VERSION 5.8 ;
BUSBITCHARS "[]" ;
DIVIDERCHAR "/" ;
UNITS
    DATABASE MICRONS 1000 ;
END UNITS

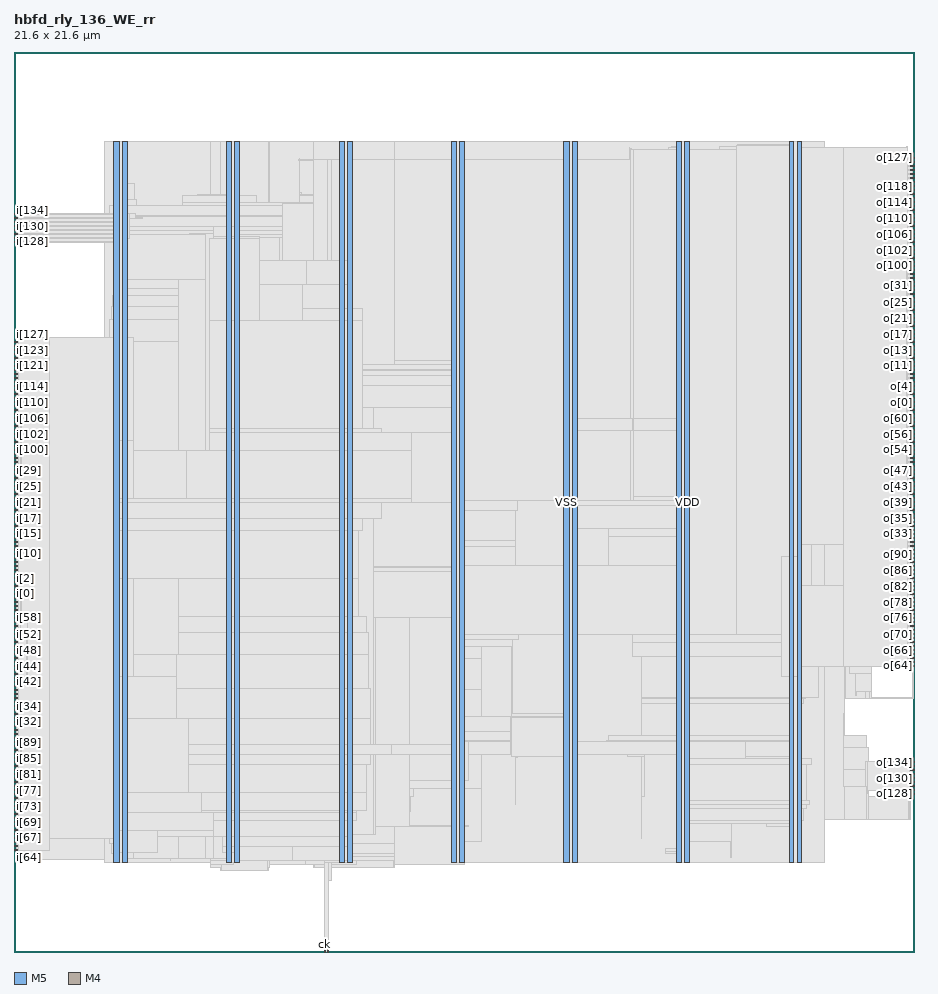
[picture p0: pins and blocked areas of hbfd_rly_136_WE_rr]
MACRO hbfd_rly_136_WE_rr
  FOREIGN hbfd_rly_136_WE_rr 0 0 ;
  CLASS BLOCK ;
  SIZE 21.6 BY 21.6 ;
  PIN ck
    DIRECTION INPUT ;
    USE SIGNAL ;
    PORT
      LAYER M5 ;
        RECT  7.44 0 7.464 0.084 ;
    END
  END ck
  PIN i[0]
    DIRECTION INPUT ;
    USE SIGNAL ;
    PORT
      LAYER M4 ;
        RECT  0 8.592 0.084 8.616 ;
    END
  END i[0]
  PIN i[100]
    DIRECTION INPUT ;
    USE SIGNAL ;
    PORT
      LAYER M4 ;
        RECT  0 12.048 0.084 12.072 ;
    END
  END i[100]
  PIN i[101]
    DIRECTION INPUT ;
    USE SIGNAL ;
    PORT
      LAYER M4 ;
        RECT  0 12.144 0.084 12.168 ;
    END
  END i[101]
  PIN i[102]
    DIRECTION INPUT ;
    USE SIGNAL ;
    PORT
      LAYER M4 ;
        RECT  0 12.24 0.084 12.264 ;
    END
  END i[102]
  PIN i[103]
    DIRECTION INPUT ;
    USE SIGNAL ;
    PORT
      LAYER M4 ;
        RECT  0 12.336 0.084 12.36 ;
    END
  END i[103]
  PIN i[104]
    DIRECTION INPUT ;
    USE SIGNAL ;
    PORT
      LAYER M4 ;
        RECT  0 12.432 0.084 12.456 ;
    END
  END i[104]
  PIN i[105]
    DIRECTION INPUT ;
    USE SIGNAL ;
    PORT
      LAYER M4 ;
        RECT  0 12.528 0.084 12.552 ;
    END
  END i[105]
  PIN i[106]
    DIRECTION INPUT ;
    USE SIGNAL ;
    PORT
      LAYER M4 ;
        RECT  0 12.624 0.084 12.648 ;
    END
  END i[106]
  PIN i[107]
    DIRECTION INPUT ;
    USE SIGNAL ;
    PORT
      LAYER M4 ;
        RECT  0 12.72 0.084 12.744 ;
    END
  END i[107]
  PIN i[108]
    DIRECTION INPUT ;
    USE SIGNAL ;
    PORT
      LAYER M4 ;
        RECT  0 12.816 0.084 12.84 ;
    END
  END i[108]
  PIN i[109]
    DIRECTION INPUT ;
    USE SIGNAL ;
    PORT
      LAYER M4 ;
        RECT  0 12.912 0.084 12.936 ;
    END
  END i[109]
  PIN i[10]
    DIRECTION INPUT ;
    USE SIGNAL ;
    PORT
      LAYER M4 ;
        RECT  0 9.552 0.084 9.576 ;
    END
  END i[10]
  PIN i[110]
    DIRECTION INPUT ;
    USE SIGNAL ;
    PORT
      LAYER M4 ;
        RECT  0 13.008 0.084 13.032 ;
    END
  END i[110]
  PIN i[111]
    DIRECTION INPUT ;
    USE SIGNAL ;
    PORT
      LAYER M4 ;
        RECT  0 13.104 0.084 13.128 ;
    END
  END i[111]
  PIN i[112]
    DIRECTION INPUT ;
    USE SIGNAL ;
    PORT
      LAYER M4 ;
        RECT  0 13.2 0.084 13.224 ;
    END
  END i[112]
  PIN i[113]
    DIRECTION INPUT ;
    USE SIGNAL ;
    PORT
      LAYER M4 ;
        RECT  0 13.296 0.084 13.32 ;
    END
  END i[113]
  PIN i[114]
    DIRECTION INPUT ;
    USE SIGNAL ;
    PORT
      LAYER M4 ;
        RECT  0 13.392 0.084 13.416 ;
    END
  END i[114]
  PIN i[115]
    DIRECTION INPUT ;
    USE SIGNAL ;
    PORT
      LAYER M4 ;
        RECT  0 13.488 0.084 13.512 ;
    END
  END i[115]
  PIN i[116]
    DIRECTION INPUT ;
    USE SIGNAL ;
    PORT
      LAYER M4 ;
        RECT  0 13.584 0.084 13.608 ;
    END
  END i[116]
  PIN i[117]
    DIRECTION INPUT ;
    USE SIGNAL ;
    PORT
      LAYER M4 ;
        RECT  0 13.68 0.084 13.704 ;
    END
  END i[117]
  PIN i[118]
    DIRECTION INPUT ;
    USE SIGNAL ;
    PORT
      LAYER M4 ;
        RECT  0 13.776 0.084 13.8 ;
    END
  END i[118]
  PIN i[119]
    DIRECTION INPUT ;
    USE SIGNAL ;
    PORT
      LAYER M4 ;
        RECT  0 13.872 0.084 13.896 ;
    END
  END i[119]
  PIN i[11]
    DIRECTION INPUT ;
    USE SIGNAL ;
    PORT
      LAYER M4 ;
        RECT  0 9.648 0.084 9.672 ;
    END
  END i[11]
  PIN i[120]
    DIRECTION INPUT ;
    USE SIGNAL ;
    PORT
      LAYER M4 ;
        RECT  0 13.968 0.084 13.992 ;
    END
  END i[120]
  PIN i[121]
    DIRECTION INPUT ;
    USE SIGNAL ;
    PORT
      LAYER M4 ;
        RECT  0 14.064 0.084 14.088 ;
    END
  END i[121]
  PIN i[122]
    DIRECTION INPUT ;
    USE SIGNAL ;
    PORT
      LAYER M4 ;
        RECT  0 14.16 0.084 14.184 ;
    END
  END i[122]
  PIN i[123]
    DIRECTION INPUT ;
    USE SIGNAL ;
    PORT
      LAYER M4 ;
        RECT  0 14.256 0.084 14.28 ;
    END
  END i[123]
  PIN i[124]
    DIRECTION INPUT ;
    USE SIGNAL ;
    PORT
      LAYER M4 ;
        RECT  0 14.352 0.084 14.376 ;
    END
  END i[124]
  PIN i[125]
    DIRECTION INPUT ;
    USE SIGNAL ;
    PORT
      LAYER M4 ;
        RECT  0 14.448 0.084 14.472 ;
    END
  END i[125]
  PIN i[126]
    DIRECTION INPUT ;
    USE SIGNAL ;
    PORT
      LAYER M4 ;
        RECT  0 14.544 0.084 14.568 ;
    END
  END i[126]
  PIN i[127]
    DIRECTION INPUT ;
    USE SIGNAL ;
    PORT
      LAYER M4 ;
        RECT  0 14.64 0.084 14.664 ;
    END
  END i[127]
  PIN i[128]
    DIRECTION INPUT ;
    USE SIGNAL ;
    PORT
      LAYER M4 ;
        RECT  0 17.04 0.084 17.064 ;
    END
  END i[128]
  PIN i[129]
    DIRECTION INPUT ;
    USE SIGNAL ;
    PORT
      LAYER M4 ;
        RECT  0 17.136 0.084 17.16 ;
    END
  END i[129]
  PIN i[12]
    DIRECTION INPUT ;
    USE SIGNAL ;
    PORT
      LAYER M4 ;
        RECT  0 9.744 0.084 9.768 ;
    END
  END i[12]
  PIN i[130]
    DIRECTION INPUT ;
    USE SIGNAL ;
    PORT
      LAYER M4 ;
        RECT  0 17.232 0.084 17.256 ;
    END
  END i[130]
  PIN i[131]
    DIRECTION INPUT ;
    USE SIGNAL ;
    PORT
      LAYER M4 ;
        RECT  0 17.328 0.084 17.352 ;
    END
  END i[131]
  PIN i[132]
    DIRECTION INPUT ;
    USE SIGNAL ;
    PORT
      LAYER M4 ;
        RECT  0 17.424 0.084 17.448 ;
    END
  END i[132]
  PIN i[133]
    DIRECTION INPUT ;
    USE SIGNAL ;
    PORT
      LAYER M4 ;
        RECT  0 17.52 0.084 17.544 ;
    END
  END i[133]
  PIN i[134]
    DIRECTION INPUT ;
    USE SIGNAL ;
    PORT
      LAYER M4 ;
        RECT  0 17.616 0.084 17.64 ;
    END
  END i[134]
  PIN i[135]
    DIRECTION INPUT ;
    USE SIGNAL ;
    PORT
      LAYER M4 ;
        RECT  0 17.712 0.084 17.736 ;
    END
  END i[135]
  PIN i[13]
    DIRECTION INPUT ;
    USE SIGNAL ;
    PORT
      LAYER M4 ;
        RECT  0 9.84 0.084 9.864 ;
    END
  END i[13]
  PIN i[14]
    DIRECTION INPUT ;
    USE SIGNAL ;
    PORT
      LAYER M4 ;
        RECT  0 9.936 0.084 9.96 ;
    END
  END i[14]
  PIN i[15]
    DIRECTION INPUT ;
    USE SIGNAL ;
    PORT
      LAYER M4 ;
        RECT  0 10.032 0.084 10.056 ;
    END
  END i[15]
  PIN i[16]
    DIRECTION INPUT ;
    USE SIGNAL ;
    PORT
      LAYER M4 ;
        RECT  0 10.128 0.084 10.152 ;
    END
  END i[16]
  PIN i[17]
    DIRECTION INPUT ;
    USE SIGNAL ;
    PORT
      LAYER M4 ;
        RECT  0 10.224 0.084 10.248 ;
    END
  END i[17]
  PIN i[18]
    DIRECTION INPUT ;
    USE SIGNAL ;
    PORT
      LAYER M4 ;
        RECT  0 10.32 0.084 10.344 ;
    END
  END i[18]
  PIN i[19]
    DIRECTION INPUT ;
    USE SIGNAL ;
    PORT
      LAYER M4 ;
        RECT  0 10.416 0.084 10.44 ;
    END
  END i[19]
  PIN i[1]
    DIRECTION INPUT ;
    USE SIGNAL ;
    PORT
      LAYER M4 ;
        RECT  0 8.688 0.084 8.712 ;
    END
  END i[1]
  PIN i[20]
    DIRECTION INPUT ;
    USE SIGNAL ;
    PORT
      LAYER M4 ;
        RECT  0 10.512 0.084 10.536 ;
    END
  END i[20]
  PIN i[21]
    DIRECTION INPUT ;
    USE SIGNAL ;
    PORT
      LAYER M4 ;
        RECT  0 10.608 0.084 10.632 ;
    END
  END i[21]
  PIN i[22]
    DIRECTION INPUT ;
    USE SIGNAL ;
    PORT
      LAYER M4 ;
        RECT  0 10.704 0.084 10.728 ;
    END
  END i[22]
  PIN i[23]
    DIRECTION INPUT ;
    USE SIGNAL ;
    PORT
      LAYER M4 ;
        RECT  0 10.8 0.084 10.824 ;
    END
  END i[23]
  PIN i[24]
    DIRECTION INPUT ;
    USE SIGNAL ;
    PORT
      LAYER M4 ;
        RECT  0 10.896 0.084 10.92 ;
    END
  END i[24]
  PIN i[25]
    DIRECTION INPUT ;
    USE SIGNAL ;
    PORT
      LAYER M4 ;
        RECT  0 10.992 0.084 11.016 ;
    END
  END i[25]
  PIN i[26]
    DIRECTION INPUT ;
    USE SIGNAL ;
    PORT
      LAYER M4 ;
        RECT  0 11.088 0.084 11.112 ;
    END
  END i[26]
  PIN i[27]
    DIRECTION INPUT ;
    USE SIGNAL ;
    PORT
      LAYER M4 ;
        RECT  0 11.184 0.084 11.208 ;
    END
  END i[27]
  PIN i[28]
    DIRECTION INPUT ;
    USE SIGNAL ;
    PORT
      LAYER M4 ;
        RECT  0 11.28 0.084 11.304 ;
    END
  END i[28]
  PIN i[29]
    DIRECTION INPUT ;
    USE SIGNAL ;
    PORT
      LAYER M4 ;
        RECT  0 11.376 0.084 11.4 ;
    END
  END i[29]
  PIN i[2]
    DIRECTION INPUT ;
    USE SIGNAL ;
    PORT
      LAYER M4 ;
        RECT  0 8.784 0.084 8.808 ;
    END
  END i[2]
  PIN i[30]
    DIRECTION INPUT ;
    USE SIGNAL ;
    PORT
      LAYER M4 ;
        RECT  0 11.472 0.084 11.496 ;
    END
  END i[30]
  PIN i[31]
    DIRECTION INPUT ;
    USE SIGNAL ;
    PORT
      LAYER M4 ;
        RECT  0 11.568 0.084 11.592 ;
    END
  END i[31]
  PIN i[32]
    DIRECTION INPUT ;
    USE SIGNAL ;
    PORT
      LAYER M4 ;
        RECT  0 5.52 0.084 5.544 ;
    END
  END i[32]
  PIN i[33]
    DIRECTION INPUT ;
    USE SIGNAL ;
    PORT
      LAYER M4 ;
        RECT  0 5.616 0.084 5.64 ;
    END
  END i[33]
  PIN i[34]
    DIRECTION INPUT ;
    USE SIGNAL ;
    PORT
      LAYER M4 ;
        RECT  0 5.712 0.084 5.736 ;
    END
  END i[34]
  PIN i[35]
    DIRECTION INPUT ;
    USE SIGNAL ;
    PORT
      LAYER M4 ;
        RECT  0 5.808 0.084 5.832 ;
    END
  END i[35]
  PIN i[36]
    DIRECTION INPUT ;
    USE SIGNAL ;
    PORT
      LAYER M4 ;
        RECT  0 5.904 0.084 5.928 ;
    END
  END i[36]
  PIN i[37]
    DIRECTION INPUT ;
    USE SIGNAL ;
    PORT
      LAYER M4 ;
        RECT  0 6 0.084 6.024 ;
    END
  END i[37]
  PIN i[38]
    DIRECTION INPUT ;
    USE SIGNAL ;
    PORT
      LAYER M4 ;
        RECT  0 6.096 0.084 6.12 ;
    END
  END i[38]
  PIN i[39]
    DIRECTION INPUT ;
    USE SIGNAL ;
    PORT
      LAYER M4 ;
        RECT  0 6.192 0.084 6.216 ;
    END
  END i[39]
  PIN i[3]
    DIRECTION INPUT ;
    USE SIGNAL ;
    PORT
      LAYER M4 ;
        RECT  0 8.88 0.084 8.904 ;
    END
  END i[3]
  PIN i[40]
    DIRECTION INPUT ;
    USE SIGNAL ;
    PORT
      LAYER M4 ;
        RECT  0 6.288 0.084 6.312 ;
    END
  END i[40]
  PIN i[41]
    DIRECTION INPUT ;
    USE SIGNAL ;
    PORT
      LAYER M4 ;
        RECT  0 6.384 0.084 6.408 ;
    END
  END i[41]
  PIN i[42]
    DIRECTION INPUT ;
    USE SIGNAL ;
    PORT
      LAYER M4 ;
        RECT  0 6.48 0.084 6.504 ;
    END
  END i[42]
  PIN i[43]
    DIRECTION INPUT ;
    USE SIGNAL ;
    PORT
      LAYER M4 ;
        RECT  0 6.576 0.084 6.6 ;
    END
  END i[43]
  PIN i[44]
    DIRECTION INPUT ;
    USE SIGNAL ;
    PORT
      LAYER M4 ;
        RECT  0 6.672 0.084 6.696 ;
    END
  END i[44]
  PIN i[45]
    DIRECTION INPUT ;
    USE SIGNAL ;
    PORT
      LAYER M4 ;
        RECT  0 6.768 0.084 6.792 ;
    END
  END i[45]
  PIN i[46]
    DIRECTION INPUT ;
    USE SIGNAL ;
    PORT
      LAYER M4 ;
        RECT  0 6.864 0.084 6.888 ;
    END
  END i[46]
  PIN i[47]
    DIRECTION INPUT ;
    USE SIGNAL ;
    PORT
      LAYER M4 ;
        RECT  0 6.96 0.084 6.984 ;
    END
  END i[47]
  PIN i[48]
    DIRECTION INPUT ;
    USE SIGNAL ;
    PORT
      LAYER M4 ;
        RECT  0 7.056 0.084 7.08 ;
    END
  END i[48]
  PIN i[49]
    DIRECTION INPUT ;
    USE SIGNAL ;
    PORT
      LAYER M4 ;
        RECT  0 7.152 0.084 7.176 ;
    END
  END i[49]
  PIN i[4]
    DIRECTION INPUT ;
    USE SIGNAL ;
    PORT
      LAYER M4 ;
        RECT  0 8.976 0.084 9 ;
    END
  END i[4]
  PIN i[50]
    DIRECTION INPUT ;
    USE SIGNAL ;
    PORT
      LAYER M4 ;
        RECT  0 7.248 0.084 7.272 ;
    END
  END i[50]
  PIN i[51]
    DIRECTION INPUT ;
    USE SIGNAL ;
    PORT
      LAYER M4 ;
        RECT  0 7.344 0.084 7.368 ;
    END
  END i[51]
  PIN i[52]
    DIRECTION INPUT ;
    USE SIGNAL ;
    PORT
      LAYER M4 ;
        RECT  0 7.44 0.084 7.464 ;
    END
  END i[52]
  PIN i[53]
    DIRECTION INPUT ;
    USE SIGNAL ;
    PORT
      LAYER M4 ;
        RECT  0 7.536 0.084 7.56 ;
    END
  END i[53]
  PIN i[54]
    DIRECTION INPUT ;
    USE SIGNAL ;
    PORT
      LAYER M4 ;
        RECT  0 7.632 0.084 7.656 ;
    END
  END i[54]
  PIN i[55]
    DIRECTION INPUT ;
    USE SIGNAL ;
    PORT
      LAYER M4 ;
        RECT  0 7.728 0.084 7.752 ;
    END
  END i[55]
  PIN i[56]
    DIRECTION INPUT ;
    USE SIGNAL ;
    PORT
      LAYER M4 ;
        RECT  0 7.824 0.084 7.848 ;
    END
  END i[56]
  PIN i[57]
    DIRECTION INPUT ;
    USE SIGNAL ;
    PORT
      LAYER M4 ;
        RECT  0 7.92 0.084 7.944 ;
    END
  END i[57]
  PIN i[58]
    DIRECTION INPUT ;
    USE SIGNAL ;
    PORT
      LAYER M4 ;
        RECT  0 8.016 0.084 8.04 ;
    END
  END i[58]
  PIN i[59]
    DIRECTION INPUT ;
    USE SIGNAL ;
    PORT
      LAYER M4 ;
        RECT  0 8.112 0.084 8.136 ;
    END
  END i[59]
  PIN i[5]
    DIRECTION INPUT ;
    USE SIGNAL ;
    PORT
      LAYER M4 ;
        RECT  0 9.072 0.084 9.096 ;
    END
  END i[5]
  PIN i[60]
    DIRECTION INPUT ;
    USE SIGNAL ;
    PORT
      LAYER M4 ;
        RECT  0 8.208 0.084 8.232 ;
    END
  END i[60]
  PIN i[61]
    DIRECTION INPUT ;
    USE SIGNAL ;
    PORT
      LAYER M4 ;
        RECT  0 8.304 0.084 8.328 ;
    END
  END i[61]
  PIN i[62]
    DIRECTION INPUT ;
    USE SIGNAL ;
    PORT
      LAYER M4 ;
        RECT  0 8.4 0.084 8.424 ;
    END
  END i[62]
  PIN i[63]
    DIRECTION INPUT ;
    USE SIGNAL ;
    PORT
      LAYER M4 ;
        RECT  0 8.496 0.084 8.52 ;
    END
  END i[63]
  PIN i[64]
    DIRECTION INPUT ;
    USE SIGNAL ;
    PORT
      LAYER M4 ;
        RECT  0 2.448 0.084 2.472 ;
    END
  END i[64]
  PIN i[65]
    DIRECTION INPUT ;
    USE SIGNAL ;
    PORT
      LAYER M4 ;
        RECT  0 2.544 0.084 2.568 ;
    END
  END i[65]
  PIN i[66]
    DIRECTION INPUT ;
    USE SIGNAL ;
    PORT
      LAYER M4 ;
        RECT  0 2.64 0.084 2.664 ;
    END
  END i[66]
  PIN i[67]
    DIRECTION INPUT ;
    USE SIGNAL ;
    PORT
      LAYER M4 ;
        RECT  0 2.736 0.084 2.76 ;
    END
  END i[67]
  PIN i[68]
    DIRECTION INPUT ;
    USE SIGNAL ;
    PORT
      LAYER M4 ;
        RECT  0 2.832 0.084 2.856 ;
    END
  END i[68]
  PIN i[69]
    DIRECTION INPUT ;
    USE SIGNAL ;
    PORT
      LAYER M4 ;
        RECT  0 2.928 0.084 2.952 ;
    END
  END i[69]
  PIN i[6]
    DIRECTION INPUT ;
    USE SIGNAL ;
    PORT
      LAYER M4 ;
        RECT  0 9.168 0.084 9.192 ;
    END
  END i[6]
  PIN i[70]
    DIRECTION INPUT ;
    USE SIGNAL ;
    PORT
      LAYER M4 ;
        RECT  0 3.024 0.084 3.048 ;
    END
  END i[70]
  PIN i[71]
    DIRECTION INPUT ;
    USE SIGNAL ;
    PORT
      LAYER M4 ;
        RECT  0 3.12 0.084 3.144 ;
    END
  END i[71]
  PIN i[72]
    DIRECTION INPUT ;
    USE SIGNAL ;
    PORT
      LAYER M4 ;
        RECT  0 3.216 0.084 3.24 ;
    END
  END i[72]
  PIN i[73]
    DIRECTION INPUT ;
    USE SIGNAL ;
    PORT
      LAYER M4 ;
        RECT  0 3.312 0.084 3.336 ;
    END
  END i[73]
  PIN i[74]
    DIRECTION INPUT ;
    USE SIGNAL ;
    PORT
      LAYER M4 ;
        RECT  0 3.408 0.084 3.432 ;
    END
  END i[74]
  PIN i[75]
    DIRECTION INPUT ;
    USE SIGNAL ;
    PORT
      LAYER M4 ;
        RECT  0 3.504 0.084 3.528 ;
    END
  END i[75]
  PIN i[76]
    DIRECTION INPUT ;
    USE SIGNAL ;
    PORT
      LAYER M4 ;
        RECT  0 3.6 0.084 3.624 ;
    END
  END i[76]
  PIN i[77]
    DIRECTION INPUT ;
    USE SIGNAL ;
    PORT
      LAYER M4 ;
        RECT  0 3.696 0.084 3.72 ;
    END
  END i[77]
  PIN i[78]
    DIRECTION INPUT ;
    USE SIGNAL ;
    PORT
      LAYER M4 ;
        RECT  0 3.792 0.084 3.816 ;
    END
  END i[78]
  PIN i[79]
    DIRECTION INPUT ;
    USE SIGNAL ;
    PORT
      LAYER M4 ;
        RECT  0 3.888 0.084 3.912 ;
    END
  END i[79]
  PIN i[7]
    DIRECTION INPUT ;
    USE SIGNAL ;
    PORT
      LAYER M4 ;
        RECT  0 9.264 0.084 9.288 ;
    END
  END i[7]
  PIN i[80]
    DIRECTION INPUT ;
    USE SIGNAL ;
    PORT
      LAYER M4 ;
        RECT  0 3.984 0.084 4.008 ;
    END
  END i[80]
  PIN i[81]
    DIRECTION INPUT ;
    USE SIGNAL ;
    PORT
      LAYER M4 ;
        RECT  0 4.08 0.084 4.104 ;
    END
  END i[81]
  PIN i[82]
    DIRECTION INPUT ;
    USE SIGNAL ;
    PORT
      LAYER M4 ;
        RECT  0 4.176 0.084 4.2 ;
    END
  END i[82]
  PIN i[83]
    DIRECTION INPUT ;
    USE SIGNAL ;
    PORT
      LAYER M4 ;
        RECT  0 4.272 0.084 4.296 ;
    END
  END i[83]
  PIN i[84]
    DIRECTION INPUT ;
    USE SIGNAL ;
    PORT
      LAYER M4 ;
        RECT  0 4.368 0.084 4.392 ;
    END
  END i[84]
  PIN i[85]
    DIRECTION INPUT ;
    USE SIGNAL ;
    PORT
      LAYER M4 ;
        RECT  0 4.464 0.084 4.488 ;
    END
  END i[85]
  PIN i[86]
    DIRECTION INPUT ;
    USE SIGNAL ;
    PORT
      LAYER M4 ;
        RECT  0 4.56 0.084 4.584 ;
    END
  END i[86]
  PIN i[87]
    DIRECTION INPUT ;
    USE SIGNAL ;
    PORT
      LAYER M4 ;
        RECT  0 4.656 0.084 4.68 ;
    END
  END i[87]
  PIN i[88]
    DIRECTION INPUT ;
    USE SIGNAL ;
    PORT
      LAYER M4 ;
        RECT  0 4.752 0.084 4.776 ;
    END
  END i[88]
  PIN i[89]
    DIRECTION INPUT ;
    USE SIGNAL ;
    PORT
      LAYER M4 ;
        RECT  0 4.848 0.084 4.872 ;
    END
  END i[89]
  PIN i[8]
    DIRECTION INPUT ;
    USE SIGNAL ;
    PORT
      LAYER M4 ;
        RECT  0 9.36 0.084 9.384 ;
    END
  END i[8]
  PIN i[90]
    DIRECTION INPUT ;
    USE SIGNAL ;
    PORT
      LAYER M4 ;
        RECT  0 4.944 0.084 4.968 ;
    END
  END i[90]
  PIN i[91]
    DIRECTION INPUT ;
    USE SIGNAL ;
    PORT
      LAYER M4 ;
        RECT  0 5.04 0.084 5.064 ;
    END
  END i[91]
  PIN i[92]
    DIRECTION INPUT ;
    USE SIGNAL ;
    PORT
      LAYER M4 ;
        RECT  0 5.136 0.084 5.16 ;
    END
  END i[92]
  PIN i[93]
    DIRECTION INPUT ;
    USE SIGNAL ;
    PORT
      LAYER M4 ;
        RECT  0 5.232 0.084 5.256 ;
    END
  END i[93]
  PIN i[94]
    DIRECTION INPUT ;
    USE SIGNAL ;
    PORT
      LAYER M4 ;
        RECT  0 5.328 0.084 5.352 ;
    END
  END i[94]
  PIN i[95]
    DIRECTION INPUT ;
    USE SIGNAL ;
    PORT
      LAYER M4 ;
        RECT  0 5.424 0.084 5.448 ;
    END
  END i[95]
  PIN i[96]
    DIRECTION INPUT ;
    USE SIGNAL ;
    PORT
      LAYER M4 ;
        RECT  0 11.664 0.084 11.688 ;
    END
  END i[96]
  PIN i[97]
    DIRECTION INPUT ;
    USE SIGNAL ;
    PORT
      LAYER M4 ;
        RECT  0 11.76 0.084 11.784 ;
    END
  END i[97]
  PIN i[98]
    DIRECTION INPUT ;
    USE SIGNAL ;
    PORT
      LAYER M4 ;
        RECT  0 11.856 0.084 11.88 ;
    END
  END i[98]
  PIN i[99]
    DIRECTION INPUT ;
    USE SIGNAL ;
    PORT
      LAYER M4 ;
        RECT  0 11.952 0.084 11.976 ;
    END
  END i[99]
  PIN i[9]
    DIRECTION INPUT ;
    USE SIGNAL ;
    PORT
      LAYER M4 ;
        RECT  0 9.456 0.084 9.48 ;
    END
  END i[9]
  PIN o[0]
    DIRECTION OUTPUT ;
    USE SIGNAL ;
    PORT
      LAYER M4 ;
        RECT  21.516 13.008 21.6 13.032 ;
    END
  END o[0]
  PIN o[100]
    DIRECTION OUTPUT ;
    USE SIGNAL ;
    PORT
      LAYER M4 ;
        RECT  21.516 16.464 21.6 16.488 ;
    END
  END o[100]
  PIN o[101]
    DIRECTION OUTPUT ;
    USE SIGNAL ;
    PORT
      LAYER M4 ;
        RECT  21.516 16.56 21.6 16.584 ;
    END
  END o[101]
  PIN o[102]
    DIRECTION OUTPUT ;
    USE SIGNAL ;
    PORT
      LAYER M4 ;
        RECT  21.516 16.656 21.6 16.68 ;
    END
  END o[102]
  PIN o[103]
    DIRECTION OUTPUT ;
    USE SIGNAL ;
    PORT
      LAYER M4 ;
        RECT  21.516 16.752 21.6 16.776 ;
    END
  END o[103]
  PIN o[104]
    DIRECTION OUTPUT ;
    USE SIGNAL ;
    PORT
      LAYER M4 ;
        RECT  21.516 16.848 21.6 16.872 ;
    END
  END o[104]
  PIN o[105]
    DIRECTION OUTPUT ;
    USE SIGNAL ;
    PORT
      LAYER M4 ;
        RECT  21.516 16.944 21.6 16.968 ;
    END
  END o[105]
  PIN o[106]
    DIRECTION OUTPUT ;
    USE SIGNAL ;
    PORT
      LAYER M4 ;
        RECT  21.516 17.04 21.6 17.064 ;
    END
  END o[106]
  PIN o[107]
    DIRECTION OUTPUT ;
    USE SIGNAL ;
    PORT
      LAYER M4 ;
        RECT  21.516 17.136 21.6 17.16 ;
    END
  END o[107]
  PIN o[108]
    DIRECTION OUTPUT ;
    USE SIGNAL ;
    PORT
      LAYER M4 ;
        RECT  21.516 17.232 21.6 17.256 ;
    END
  END o[108]
  PIN o[109]
    DIRECTION OUTPUT ;
    USE SIGNAL ;
    PORT
      LAYER M4 ;
        RECT  21.516 17.328 21.6 17.352 ;
    END
  END o[109]
  PIN o[10]
    DIRECTION OUTPUT ;
    USE SIGNAL ;
    PORT
      LAYER M4 ;
        RECT  21.516 13.968 21.6 13.992 ;
    END
  END o[10]
  PIN o[110]
    DIRECTION OUTPUT ;
    USE SIGNAL ;
    PORT
      LAYER M4 ;
        RECT  21.516 17.424 21.6 17.448 ;
    END
  END o[110]
  PIN o[111]
    DIRECTION OUTPUT ;
    USE SIGNAL ;
    PORT
      LAYER M4 ;
        RECT  21.516 17.52 21.6 17.544 ;
    END
  END o[111]
  PIN o[112]
    DIRECTION OUTPUT ;
    USE SIGNAL ;
    PORT
      LAYER M4 ;
        RECT  21.516 17.616 21.6 17.64 ;
    END
  END o[112]
  PIN o[113]
    DIRECTION OUTPUT ;
    USE SIGNAL ;
    PORT
      LAYER M4 ;
        RECT  21.516 17.712 21.6 17.736 ;
    END
  END o[113]
  PIN o[114]
    DIRECTION OUTPUT ;
    USE SIGNAL ;
    PORT
      LAYER M4 ;
        RECT  21.516 17.808 21.6 17.832 ;
    END
  END o[114]
  PIN o[115]
    DIRECTION OUTPUT ;
    USE SIGNAL ;
    PORT
      LAYER M4 ;
        RECT  21.516 17.904 21.6 17.928 ;
    END
  END o[115]
  PIN o[116]
    DIRECTION OUTPUT ;
    USE SIGNAL ;
    PORT
      LAYER M4 ;
        RECT  21.516 18 21.6 18.024 ;
    END
  END o[116]
  PIN o[117]
    DIRECTION OUTPUT ;
    USE SIGNAL ;
    PORT
      LAYER M4 ;
        RECT  21.516 18.096 21.6 18.12 ;
    END
  END o[117]
  PIN o[118]
    DIRECTION OUTPUT ;
    USE SIGNAL ;
    PORT
      LAYER M4 ;
        RECT  21.516 18.192 21.6 18.216 ;
    END
  END o[118]
  PIN o[119]
    DIRECTION OUTPUT ;
    USE SIGNAL ;
    PORT
      LAYER M4 ;
        RECT  21.516 18.288 21.6 18.312 ;
    END
  END o[119]
  PIN o[11]
    DIRECTION OUTPUT ;
    USE SIGNAL ;
    PORT
      LAYER M4 ;
        RECT  21.516 14.064 21.6 14.088 ;
    END
  END o[11]
  PIN o[120]
    DIRECTION OUTPUT ;
    USE SIGNAL ;
    PORT
      LAYER M4 ;
        RECT  21.516 18.384 21.6 18.408 ;
    END
  END o[120]
  PIN o[121]
    DIRECTION OUTPUT ;
    USE SIGNAL ;
    PORT
      LAYER M4 ;
        RECT  21.516 18.48 21.6 18.504 ;
    END
  END o[121]
  PIN o[122]
    DIRECTION OUTPUT ;
    USE SIGNAL ;
    PORT
      LAYER M4 ;
        RECT  21.516 18.576 21.6 18.6 ;
    END
  END o[122]
  PIN o[123]
    DIRECTION OUTPUT ;
    USE SIGNAL ;
    PORT
      LAYER M4 ;
        RECT  21.516 18.672 21.6 18.696 ;
    END
  END o[123]
  PIN o[124]
    DIRECTION OUTPUT ;
    USE SIGNAL ;
    PORT
      LAYER M4 ;
        RECT  21.516 18.768 21.6 18.792 ;
    END
  END o[124]
  PIN o[125]
    DIRECTION OUTPUT ;
    USE SIGNAL ;
    PORT
      LAYER M4 ;
        RECT  21.516 18.864 21.6 18.888 ;
    END
  END o[125]
  PIN o[126]
    DIRECTION OUTPUT ;
    USE SIGNAL ;
    PORT
      LAYER M4 ;
        RECT  21.516 18.96 21.6 18.984 ;
    END
  END o[126]
  PIN o[127]
    DIRECTION OUTPUT ;
    USE SIGNAL ;
    PORT
      LAYER M4 ;
        RECT  21.516 19.056 21.6 19.08 ;
    END
  END o[127]
  PIN o[128]
    DIRECTION OUTPUT ;
    USE SIGNAL ;
    PORT
      LAYER M4 ;
        RECT  21.516 3.792 21.6 3.816 ;
    END
  END o[128]
  PIN o[129]
    DIRECTION OUTPUT ;
    USE SIGNAL ;
    PORT
      LAYER M4 ;
        RECT  21.516 3.888 21.6 3.912 ;
    END
  END o[129]
  PIN o[12]
    DIRECTION OUTPUT ;
    USE SIGNAL ;
    PORT
      LAYER M4 ;
        RECT  21.516 14.16 21.6 14.184 ;
    END
  END o[12]
  PIN o[130]
    DIRECTION OUTPUT ;
    USE SIGNAL ;
    PORT
      LAYER M4 ;
        RECT  21.516 3.984 21.6 4.008 ;
    END
  END o[130]
  PIN o[131]
    DIRECTION OUTPUT ;
    USE SIGNAL ;
    PORT
      LAYER M4 ;
        RECT  21.516 4.08 21.6 4.104 ;
    END
  END o[131]
  PIN o[132]
    DIRECTION OUTPUT ;
    USE SIGNAL ;
    PORT
      LAYER M4 ;
        RECT  21.516 4.176 21.6 4.2 ;
    END
  END o[132]
  PIN o[133]
    DIRECTION OUTPUT ;
    USE SIGNAL ;
    PORT
      LAYER M4 ;
        RECT  21.516 4.272 21.6 4.296 ;
    END
  END o[133]
  PIN o[134]
    DIRECTION OUTPUT ;
    USE SIGNAL ;
    PORT
      LAYER M4 ;
        RECT  21.516 4.368 21.6 4.392 ;
    END
  END o[134]
  PIN o[135]
    DIRECTION OUTPUT ;
    USE SIGNAL ;
    PORT
      LAYER M4 ;
        RECT  21.516 4.464 21.6 4.488 ;
    END
  END o[135]
  PIN o[13]
    DIRECTION OUTPUT ;
    USE SIGNAL ;
    PORT
      LAYER M4 ;
        RECT  21.516 14.256 21.6 14.28 ;
    END
  END o[13]
  PIN o[14]
    DIRECTION OUTPUT ;
    USE SIGNAL ;
    PORT
      LAYER M4 ;
        RECT  21.516 14.352 21.6 14.376 ;
    END
  END o[14]
  PIN o[15]
    DIRECTION OUTPUT ;
    USE SIGNAL ;
    PORT
      LAYER M4 ;
        RECT  21.516 14.448 21.6 14.472 ;
    END
  END o[15]
  PIN o[16]
    DIRECTION OUTPUT ;
    USE SIGNAL ;
    PORT
      LAYER M4 ;
        RECT  21.516 14.544 21.6 14.568 ;
    END
  END o[16]
  PIN o[17]
    DIRECTION OUTPUT ;
    USE SIGNAL ;
    PORT
      LAYER M4 ;
        RECT  21.516 14.64 21.6 14.664 ;
    END
  END o[17]
  PIN o[18]
    DIRECTION OUTPUT ;
    USE SIGNAL ;
    PORT
      LAYER M4 ;
        RECT  21.516 14.736 21.6 14.76 ;
    END
  END o[18]
  PIN o[19]
    DIRECTION OUTPUT ;
    USE SIGNAL ;
    PORT
      LAYER M4 ;
        RECT  21.516 14.832 21.6 14.856 ;
    END
  END o[19]
  PIN o[1]
    DIRECTION OUTPUT ;
    USE SIGNAL ;
    PORT
      LAYER M4 ;
        RECT  21.516 13.104 21.6 13.128 ;
    END
  END o[1]
  PIN o[20]
    DIRECTION OUTPUT ;
    USE SIGNAL ;
    PORT
      LAYER M4 ;
        RECT  21.516 14.928 21.6 14.952 ;
    END
  END o[20]
  PIN o[21]
    DIRECTION OUTPUT ;
    USE SIGNAL ;
    PORT
      LAYER M4 ;
        RECT  21.516 15.024 21.6 15.048 ;
    END
  END o[21]
  PIN o[22]
    DIRECTION OUTPUT ;
    USE SIGNAL ;
    PORT
      LAYER M4 ;
        RECT  21.516 15.12 21.6 15.144 ;
    END
  END o[22]
  PIN o[23]
    DIRECTION OUTPUT ;
    USE SIGNAL ;
    PORT
      LAYER M4 ;
        RECT  21.516 15.216 21.6 15.24 ;
    END
  END o[23]
  PIN o[24]
    DIRECTION OUTPUT ;
    USE SIGNAL ;
    PORT
      LAYER M4 ;
        RECT  21.516 15.312 21.6 15.336 ;
    END
  END o[24]
  PIN o[25]
    DIRECTION OUTPUT ;
    USE SIGNAL ;
    PORT
      LAYER M4 ;
        RECT  21.516 15.408 21.6 15.432 ;
    END
  END o[25]
  PIN o[26]
    DIRECTION OUTPUT ;
    USE SIGNAL ;
    PORT
      LAYER M4 ;
        RECT  21.516 15.504 21.6 15.528 ;
    END
  END o[26]
  PIN o[27]
    DIRECTION OUTPUT ;
    USE SIGNAL ;
    PORT
      LAYER M4 ;
        RECT  21.516 15.6 21.6 15.624 ;
    END
  END o[27]
  PIN o[28]
    DIRECTION OUTPUT ;
    USE SIGNAL ;
    PORT
      LAYER M4 ;
        RECT  21.516 15.696 21.6 15.72 ;
    END
  END o[28]
  PIN o[29]
    DIRECTION OUTPUT ;
    USE SIGNAL ;
    PORT
      LAYER M4 ;
        RECT  21.516 15.792 21.6 15.816 ;
    END
  END o[29]
  PIN o[2]
    DIRECTION OUTPUT ;
    USE SIGNAL ;
    PORT
      LAYER M4 ;
        RECT  21.516 13.2 21.6 13.224 ;
    END
  END o[2]
  PIN o[30]
    DIRECTION OUTPUT ;
    USE SIGNAL ;
    PORT
      LAYER M4 ;
        RECT  21.516 15.888 21.6 15.912 ;
    END
  END o[30]
  PIN o[31]
    DIRECTION OUTPUT ;
    USE SIGNAL ;
    PORT
      LAYER M4 ;
        RECT  21.516 15.984 21.6 16.008 ;
    END
  END o[31]
  PIN o[32]
    DIRECTION OUTPUT ;
    USE SIGNAL ;
    PORT
      LAYER M4 ;
        RECT  21.516 9.936 21.6 9.96 ;
    END
  END o[32]
  PIN o[33]
    DIRECTION OUTPUT ;
    USE SIGNAL ;
    PORT
      LAYER M4 ;
        RECT  21.516 10.032 21.6 10.056 ;
    END
  END o[33]
  PIN o[34]
    DIRECTION OUTPUT ;
    USE SIGNAL ;
    PORT
      LAYER M4 ;
        RECT  21.516 10.128 21.6 10.152 ;
    END
  END o[34]
  PIN o[35]
    DIRECTION OUTPUT ;
    USE SIGNAL ;
    PORT
      LAYER M4 ;
        RECT  21.516 10.224 21.6 10.248 ;
    END
  END o[35]
  PIN o[36]
    DIRECTION OUTPUT ;
    USE SIGNAL ;
    PORT
      LAYER M4 ;
        RECT  21.516 10.32 21.6 10.344 ;
    END
  END o[36]
  PIN o[37]
    DIRECTION OUTPUT ;
    USE SIGNAL ;
    PORT
      LAYER M4 ;
        RECT  21.516 10.416 21.6 10.44 ;
    END
  END o[37]
  PIN o[38]
    DIRECTION OUTPUT ;
    USE SIGNAL ;
    PORT
      LAYER M4 ;
        RECT  21.516 10.512 21.6 10.536 ;
    END
  END o[38]
  PIN o[39]
    DIRECTION OUTPUT ;
    USE SIGNAL ;
    PORT
      LAYER M4 ;
        RECT  21.516 10.608 21.6 10.632 ;
    END
  END o[39]
  PIN o[3]
    DIRECTION OUTPUT ;
    USE SIGNAL ;
    PORT
      LAYER M4 ;
        RECT  21.516 13.296 21.6 13.32 ;
    END
  END o[3]
  PIN o[40]
    DIRECTION OUTPUT ;
    USE SIGNAL ;
    PORT
      LAYER M4 ;
        RECT  21.516 10.704 21.6 10.728 ;
    END
  END o[40]
  PIN o[41]
    DIRECTION OUTPUT ;
    USE SIGNAL ;
    PORT
      LAYER M4 ;
        RECT  21.516 10.8 21.6 10.824 ;
    END
  END o[41]
  PIN o[42]
    DIRECTION OUTPUT ;
    USE SIGNAL ;
    PORT
      LAYER M4 ;
        RECT  21.516 10.896 21.6 10.92 ;
    END
  END o[42]
  PIN o[43]
    DIRECTION OUTPUT ;
    USE SIGNAL ;
    PORT
      LAYER M4 ;
        RECT  21.516 10.992 21.6 11.016 ;
    END
  END o[43]
  PIN o[44]
    DIRECTION OUTPUT ;
    USE SIGNAL ;
    PORT
      LAYER M4 ;
        RECT  21.516 11.088 21.6 11.112 ;
    END
  END o[44]
  PIN o[45]
    DIRECTION OUTPUT ;
    USE SIGNAL ;
    PORT
      LAYER M4 ;
        RECT  21.516 11.184 21.6 11.208 ;
    END
  END o[45]
  PIN o[46]
    DIRECTION OUTPUT ;
    USE SIGNAL ;
    PORT
      LAYER M4 ;
        RECT  21.516 11.28 21.6 11.304 ;
    END
  END o[46]
  PIN o[47]
    DIRECTION OUTPUT ;
    USE SIGNAL ;
    PORT
      LAYER M4 ;
        RECT  21.516 11.376 21.6 11.4 ;
    END
  END o[47]
  PIN o[48]
    DIRECTION OUTPUT ;
    USE SIGNAL ;
    PORT
      LAYER M4 ;
        RECT  21.516 11.472 21.6 11.496 ;
    END
  END o[48]
  PIN o[49]
    DIRECTION OUTPUT ;
    USE SIGNAL ;
    PORT
      LAYER M4 ;
        RECT  21.516 11.568 21.6 11.592 ;
    END
  END o[49]
  PIN o[4]
    DIRECTION OUTPUT ;
    USE SIGNAL ;
    PORT
      LAYER M4 ;
        RECT  21.516 13.392 21.6 13.416 ;
    END
  END o[4]
  PIN o[50]
    DIRECTION OUTPUT ;
    USE SIGNAL ;
    PORT
      LAYER M4 ;
        RECT  21.516 11.664 21.6 11.688 ;
    END
  END o[50]
  PIN o[51]
    DIRECTION OUTPUT ;
    USE SIGNAL ;
    PORT
      LAYER M4 ;
        RECT  21.516 11.76 21.6 11.784 ;
    END
  END o[51]
  PIN o[52]
    DIRECTION OUTPUT ;
    USE SIGNAL ;
    PORT
      LAYER M4 ;
        RECT  21.516 11.856 21.6 11.88 ;
    END
  END o[52]
  PIN o[53]
    DIRECTION OUTPUT ;
    USE SIGNAL ;
    PORT
      LAYER M4 ;
        RECT  21.516 11.952 21.6 11.976 ;
    END
  END o[53]
  PIN o[54]
    DIRECTION OUTPUT ;
    USE SIGNAL ;
    PORT
      LAYER M4 ;
        RECT  21.516 12.048 21.6 12.072 ;
    END
  END o[54]
  PIN o[55]
    DIRECTION OUTPUT ;
    USE SIGNAL ;
    PORT
      LAYER M4 ;
        RECT  21.516 12.144 21.6 12.168 ;
    END
  END o[55]
  PIN o[56]
    DIRECTION OUTPUT ;
    USE SIGNAL ;
    PORT
      LAYER M4 ;
        RECT  21.516 12.24 21.6 12.264 ;
    END
  END o[56]
  PIN o[57]
    DIRECTION OUTPUT ;
    USE SIGNAL ;
    PORT
      LAYER M4 ;
        RECT  21.516 12.336 21.6 12.36 ;
    END
  END o[57]
  PIN o[58]
    DIRECTION OUTPUT ;
    USE SIGNAL ;
    PORT
      LAYER M4 ;
        RECT  21.516 12.432 21.6 12.456 ;
    END
  END o[58]
  PIN o[59]
    DIRECTION OUTPUT ;
    USE SIGNAL ;
    PORT
      LAYER M4 ;
        RECT  21.516 12.528 21.6 12.552 ;
    END
  END o[59]
  PIN o[5]
    DIRECTION OUTPUT ;
    USE SIGNAL ;
    PORT
      LAYER M4 ;
        RECT  21.516 13.488 21.6 13.512 ;
    END
  END o[5]
  PIN o[60]
    DIRECTION OUTPUT ;
    USE SIGNAL ;
    PORT
      LAYER M4 ;
        RECT  21.516 12.624 21.6 12.648 ;
    END
  END o[60]
  PIN o[61]
    DIRECTION OUTPUT ;
    USE SIGNAL ;
    PORT
      LAYER M4 ;
        RECT  21.516 12.72 21.6 12.744 ;
    END
  END o[61]
  PIN o[62]
    DIRECTION OUTPUT ;
    USE SIGNAL ;
    PORT
      LAYER M4 ;
        RECT  21.516 12.816 21.6 12.84 ;
    END
  END o[62]
  PIN o[63]
    DIRECTION OUTPUT ;
    USE SIGNAL ;
    PORT
      LAYER M4 ;
        RECT  21.516 12.912 21.6 12.936 ;
    END
  END o[63]
  PIN o[64]
    DIRECTION OUTPUT ;
    USE SIGNAL ;
    PORT
      LAYER M4 ;
        RECT  21.516 6.864 21.6 6.888 ;
    END
  END o[64]
  PIN o[65]
    DIRECTION OUTPUT ;
    USE SIGNAL ;
    PORT
      LAYER M4 ;
        RECT  21.516 6.96 21.6 6.984 ;
    END
  END o[65]
  PIN o[66]
    DIRECTION OUTPUT ;
    USE SIGNAL ;
    PORT
      LAYER M4 ;
        RECT  21.516 7.056 21.6 7.08 ;
    END
  END o[66]
  PIN o[67]
    DIRECTION OUTPUT ;
    USE SIGNAL ;
    PORT
      LAYER M4 ;
        RECT  21.516 7.152 21.6 7.176 ;
    END
  END o[67]
  PIN o[68]
    DIRECTION OUTPUT ;
    USE SIGNAL ;
    PORT
      LAYER M4 ;
        RECT  21.516 7.248 21.6 7.272 ;
    END
  END o[68]
  PIN o[69]
    DIRECTION OUTPUT ;
    USE SIGNAL ;
    PORT
      LAYER M4 ;
        RECT  21.516 7.344 21.6 7.368 ;
    END
  END o[69]
  PIN o[6]
    DIRECTION OUTPUT ;
    USE SIGNAL ;
    PORT
      LAYER M4 ;
        RECT  21.516 13.584 21.6 13.608 ;
    END
  END o[6]
  PIN o[70]
    DIRECTION OUTPUT ;
    USE SIGNAL ;
    PORT
      LAYER M4 ;
        RECT  21.516 7.44 21.6 7.464 ;
    END
  END o[70]
  PIN o[71]
    DIRECTION OUTPUT ;
    USE SIGNAL ;
    PORT
      LAYER M4 ;
        RECT  21.516 7.536 21.6 7.56 ;
    END
  END o[71]
  PIN o[72]
    DIRECTION OUTPUT ;
    USE SIGNAL ;
    PORT
      LAYER M4 ;
        RECT  21.516 7.632 21.6 7.656 ;
    END
  END o[72]
  PIN o[73]
    DIRECTION OUTPUT ;
    USE SIGNAL ;
    PORT
      LAYER M4 ;
        RECT  21.516 7.728 21.6 7.752 ;
    END
  END o[73]
  PIN o[74]
    DIRECTION OUTPUT ;
    USE SIGNAL ;
    PORT
      LAYER M4 ;
        RECT  21.516 7.824 21.6 7.848 ;
    END
  END o[74]
  PIN o[75]
    DIRECTION OUTPUT ;
    USE SIGNAL ;
    PORT
      LAYER M4 ;
        RECT  21.516 7.92 21.6 7.944 ;
    END
  END o[75]
  PIN o[76]
    DIRECTION OUTPUT ;
    USE SIGNAL ;
    PORT
      LAYER M4 ;
        RECT  21.516 8.016 21.6 8.04 ;
    END
  END o[76]
  PIN o[77]
    DIRECTION OUTPUT ;
    USE SIGNAL ;
    PORT
      LAYER M4 ;
        RECT  21.516 8.112 21.6 8.136 ;
    END
  END o[77]
  PIN o[78]
    DIRECTION OUTPUT ;
    USE SIGNAL ;
    PORT
      LAYER M4 ;
        RECT  21.516 8.208 21.6 8.232 ;
    END
  END o[78]
  PIN o[79]
    DIRECTION OUTPUT ;
    USE SIGNAL ;
    PORT
      LAYER M4 ;
        RECT  21.516 8.304 21.6 8.328 ;
    END
  END o[79]
  PIN o[7]
    DIRECTION OUTPUT ;
    USE SIGNAL ;
    PORT
      LAYER M4 ;
        RECT  21.516 13.68 21.6 13.704 ;
    END
  END o[7]
  PIN o[80]
    DIRECTION OUTPUT ;
    USE SIGNAL ;
    PORT
      LAYER M4 ;
        RECT  21.516 8.4 21.6 8.424 ;
    END
  END o[80]
  PIN o[81]
    DIRECTION OUTPUT ;
    USE SIGNAL ;
    PORT
      LAYER M4 ;
        RECT  21.516 8.496 21.6 8.52 ;
    END
  END o[81]
  PIN o[82]
    DIRECTION OUTPUT ;
    USE SIGNAL ;
    PORT
      LAYER M4 ;
        RECT  21.516 8.592 21.6 8.616 ;
    END
  END o[82]
  PIN o[83]
    DIRECTION OUTPUT ;
    USE SIGNAL ;
    PORT
      LAYER M4 ;
        RECT  21.516 8.688 21.6 8.712 ;
    END
  END o[83]
  PIN o[84]
    DIRECTION OUTPUT ;
    USE SIGNAL ;
    PORT
      LAYER M4 ;
        RECT  21.516 8.784 21.6 8.808 ;
    END
  END o[84]
  PIN o[85]
    DIRECTION OUTPUT ;
    USE SIGNAL ;
    PORT
      LAYER M4 ;
        RECT  21.516 8.88 21.6 8.904 ;
    END
  END o[85]
  PIN o[86]
    DIRECTION OUTPUT ;
    USE SIGNAL ;
    PORT
      LAYER M4 ;
        RECT  21.516 8.976 21.6 9 ;
    END
  END o[86]
  PIN o[87]
    DIRECTION OUTPUT ;
    USE SIGNAL ;
    PORT
      LAYER M4 ;
        RECT  21.516 9.072 21.6 9.096 ;
    END
  END o[87]
  PIN o[88]
    DIRECTION OUTPUT ;
    USE SIGNAL ;
    PORT
      LAYER M4 ;
        RECT  21.516 9.168 21.6 9.192 ;
    END
  END o[88]
  PIN o[89]
    DIRECTION OUTPUT ;
    USE SIGNAL ;
    PORT
      LAYER M4 ;
        RECT  21.516 9.264 21.6 9.288 ;
    END
  END o[89]
  PIN o[8]
    DIRECTION OUTPUT ;
    USE SIGNAL ;
    PORT
      LAYER M4 ;
        RECT  21.516 13.776 21.6 13.8 ;
    END
  END o[8]
  PIN o[90]
    DIRECTION OUTPUT ;
    USE SIGNAL ;
    PORT
      LAYER M4 ;
        RECT  21.516 9.36 21.6 9.384 ;
    END
  END o[90]
  PIN o[91]
    DIRECTION OUTPUT ;
    USE SIGNAL ;
    PORT
      LAYER M4 ;
        RECT  21.516 9.456 21.6 9.48 ;
    END
  END o[91]
  PIN o[92]
    DIRECTION OUTPUT ;
    USE SIGNAL ;
    PORT
      LAYER M4 ;
        RECT  21.516 9.552 21.6 9.576 ;
    END
  END o[92]
  PIN o[93]
    DIRECTION OUTPUT ;
    USE SIGNAL ;
    PORT
      LAYER M4 ;
        RECT  21.516 9.648 21.6 9.672 ;
    END
  END o[93]
  PIN o[94]
    DIRECTION OUTPUT ;
    USE SIGNAL ;
    PORT
      LAYER M4 ;
        RECT  21.516 9.744 21.6 9.768 ;
    END
  END o[94]
  PIN o[95]
    DIRECTION OUTPUT ;
    USE SIGNAL ;
    PORT
      LAYER M4 ;
        RECT  21.516 9.84 21.6 9.864 ;
    END
  END o[95]
  PIN o[96]
    DIRECTION OUTPUT ;
    USE SIGNAL ;
    PORT
      LAYER M4 ;
        RECT  21.516 16.08 21.6 16.104 ;
    END
  END o[96]
  PIN o[97]
    DIRECTION OUTPUT ;
    USE SIGNAL ;
    PORT
      LAYER M4 ;
        RECT  21.516 16.176 21.6 16.2 ;
    END
  END o[97]
  PIN o[98]
    DIRECTION OUTPUT ;
    USE SIGNAL ;
    PORT
      LAYER M4 ;
        RECT  21.516 16.272 21.6 16.296 ;
    END
  END o[98]
  PIN o[99]
    DIRECTION OUTPUT ;
    USE SIGNAL ;
    PORT
      LAYER M4 ;
        RECT  21.516 16.368 21.6 16.392 ;
    END
  END o[99]
  PIN o[9]
    DIRECTION OUTPUT ;
    USE SIGNAL ;
    PORT
      LAYER M4 ;
        RECT  21.516 13.872 21.6 13.896 ;
    END
  END o[9]
  PIN rs
    DIRECTION INPUT ;
    USE SIGNAL ;
    PORT
      LAYER M5 ;
        RECT  7.536 0 7.56 0.084 ;
    END
  END rs
  PIN rso
    DIRECTION OUTPUT ;
    USE SIGNAL ;
    PORT
      LAYER M4 ;
        RECT  21.516 4.56 21.6 4.584 ;
    END
  END rso
  PIN VDD
    DIRECTION INOUT ;
    USE POWER ;
    PORT
      LAYER M5 ;
        RECT  18.792 2.151 18.912 19.449 ;
        RECT  16.092 2.151 16.212 19.449 ;
        RECT  13.392 2.151 13.512 19.449 ;
        RECT  10.692 2.151 10.812 19.449 ;
        RECT  7.992 2.151 8.112 19.449 ;
        RECT  5.292 2.151 5.412 19.449 ;
        RECT  2.592 2.151 2.712 19.449 ;
    END
  END VDD
  PIN VSS
    DIRECTION INOUT ;
    USE GROUND ;
    PORT
      LAYER M5 ;
        RECT  18.6 2.137 18.72 19.463 ;
        RECT  15.9 2.137 16.02 19.463 ;
        RECT  13.2 2.137 13.32 19.463 ;
        RECT  10.5 2.137 10.62 19.463 ;
        RECT  7.8 2.137 7.92 19.463 ;
        RECT  5.1 2.137 5.22 19.463 ;
        RECT  2.4 2.137 2.52 19.463 ;
    END
  END VSS
  # OT_OBS_CLOSED layer=M5 d_um=1.536 added=18
  OBS
    LAYER RVTN ;
     RECT  2.16 2.16 19.44 2.295 ;
     RECT  2.16 2.565 19.44 2.835 ;
     RECT  2.16 3.105 19.44 3.375 ;
     RECT  2.16 3.645 19.44 3.915 ;
     RECT  2.16 4.185 19.44 4.455 ;
     RECT  2.16 4.725 19.44 4.995 ;
     RECT  2.16 5.265 19.44 5.535 ;
     RECT  2.16 5.805 19.44 6.075 ;
     RECT  2.16 6.345 19.44 6.615 ;
     RECT  2.16 6.885 19.44 7.155 ;
     RECT  2.16 7.425 19.44 7.695 ;
     RECT  2.16 7.965 19.44 8.235 ;
     RECT  2.16 8.505 19.44 8.775 ;
     RECT  2.16 9.045 19.44 9.315 ;
     RECT  2.16 9.585 19.44 9.855 ;
     RECT  2.16 10.125 19.44 10.395 ;
     RECT  2.16 10.665 19.44 10.935 ;
     RECT  2.16 11.205 19.44 11.475 ;
     RECT  2.16 11.745 19.44 12.015 ;
     RECT  2.16 12.285 19.44 12.555 ;
     RECT  2.16 12.825 19.44 13.095 ;
     RECT  2.16 13.365 19.44 13.635 ;
     RECT  2.16 13.905 19.44 14.175 ;
     RECT  2.16 14.445 19.44 14.715 ;
     RECT  2.16 14.985 19.44 15.255 ;
     RECT  2.16 15.525 19.44 15.795 ;
     RECT  2.16 16.065 19.44 16.335 ;
     RECT  2.16 16.605 19.44 16.875 ;
     RECT  2.16 17.145 19.44 17.415 ;
     RECT  2.16 17.685 19.44 17.955 ;
     RECT  2.16 18.225 19.44 18.495 ;
     RECT  2.16 18.765 19.44 19.035 ;
     RECT  2.16 19.305 19.44 19.44 ;
    LAYER RVTP ;
     RECT  2.16 2.295 19.44 2.565 ;
     RECT  2.16 2.835 19.44 3.105 ;
     RECT  2.16 3.375 19.44 3.645 ;
     RECT  2.16 3.915 19.44 4.185 ;
     RECT  2.16 4.455 19.44 4.725 ;
     RECT  2.16 4.995 19.44 5.265 ;
     RECT  2.16 5.535 19.44 5.805 ;
     RECT  2.16 6.075 19.44 6.345 ;
     RECT  2.16 6.615 19.44 6.885 ;
     RECT  2.16 7.155 19.44 7.425 ;
     RECT  2.16 7.695 19.44 7.965 ;
     RECT  2.16 8.235 19.44 8.505 ;
     RECT  2.16 8.775 19.44 9.045 ;
     RECT  2.16 9.315 19.44 9.585 ;
     RECT  2.16 9.855 19.44 10.125 ;
     RECT  2.16 10.395 19.44 10.665 ;
     RECT  2.16 10.935 19.44 11.205 ;
     RECT  2.16 11.475 19.44 11.745 ;
     RECT  2.16 12.015 19.44 12.285 ;
     RECT  2.16 12.555 19.44 12.825 ;
     RECT  2.16 13.095 19.44 13.365 ;
     RECT  2.16 13.635 19.44 13.905 ;
     RECT  2.16 14.175 19.44 14.445 ;
     RECT  2.16 14.715 19.44 14.985 ;
     RECT  2.16 15.255 19.44 15.525 ;
     RECT  2.16 15.795 19.44 16.065 ;
     RECT  2.16 16.335 19.44 16.605 ;
     RECT  2.16 16.875 19.44 17.145 ;
     RECT  2.16 17.415 19.44 17.685 ;
     RECT  2.16 17.955 19.44 18.225 ;
     RECT  2.16 18.495 19.44 18.765 ;
     RECT  2.16 19.035 19.44 19.305 ;
    LAYER M1 ;
     RECT  2.16 2.151 19.44 19.449 ;
    LAYER M2 ;
     RECT  0.103 2.268 0.139 2.826 ;
     RECT  0.139 2.232 0.175 2.826 ;
     RECT  0.103 7.902 0.203 7.92 ;
     RECT  0.175 10.791 0.275 10.809 ;
     RECT  0.175 2.232 0.347 3.132 ;
     RECT  0.463 5.544 0.535 5.562 ;
     RECT  0.103 12.492 0.535 12.51 ;
     RECT  0.103 3.96 0.823 3.978 ;
     RECT  0.823 3.96 1.723 4.482 ;
     RECT  0.535 5.544 1.723 5.598 ;
     RECT  0.347 2.232 2.16 3.096 ;
     RECT  1.723 3.96 2.16 5.598 ;
     RECT  0.103 6.624 2.16 6.642 ;
     RECT  0.535 9.09 2.16 9.108 ;
     RECT  0.247 9.9 2.16 9.918 ;
     RECT  1.975 11.52 2.16 11.538 ;
     RECT  0.535 12.492 2.16 12.654 ;
     RECT  0.103 17.082 2.16 17.1 ;
     RECT  2.16 2.151 4.711 19.449 ;
     RECT  4.711 2.034 4.963 19.449 ;
     RECT  4.963 1.962 6.107 19.449 ;
     RECT  6.107 2.034 6.143 19.449 ;
     RECT  6.143 2.106 7.195 19.449 ;
     RECT  7.195 2.034 9.131 19.449 ;
     RECT  9.131 2.106 10.823 19.449 ;
     RECT  10.823 2.151 19.44 19.449 ;
     RECT  19.44 3.186 19.931 14.508 ;
     RECT  19.44 15.264 19.931 17.784 ;
     RECT  19.931 6.084 19.967 14.508 ;
     RECT  19.967 6.084 20.435 12.078 ;
     RECT  19.967 12.87 20.435 14.202 ;
     RECT  19.931 3.186 20.471 5.184 ;
     RECT  20.471 3.186 20.507 4.914 ;
     RECT  20.435 8.244 20.507 12.078 ;
     RECT  20.435 12.906 20.507 14.202 ;
     RECT  19.931 15.534 20.507 17.784 ;
     RECT  20.435 6.084 20.543 7.344 ;
     RECT  20.507 8.784 20.543 9.378 ;
     RECT  20.507 10.368 20.543 12.078 ;
     RECT  20.507 13.95 20.543 14.202 ;
     RECT  20.507 17.694 20.543 17.784 ;
     RECT  20.543 6.084 20.579 6.264 ;
     RECT  20.543 8.784 20.579 8.802 ;
     RECT  20.543 17.766 20.579 17.784 ;
     RECT  20.543 10.476 21.271 10.764 ;
     RECT  20.507 15.534 21.271 16.164 ;
     RECT  21.163 18.468 21.271 18.486 ;
     RECT  21.271 18.468 21.307 18.756 ;
     RECT  21.271 10.476 21.343 11.034 ;
     RECT  20.543 11.916 21.343 11.934 ;
     RECT  21.271 15.3 21.343 16.164 ;
     RECT  21.343 15.228 21.379 16.164 ;
     RECT  21.343 10.476 21.415 11.934 ;
     RECT  20.507 12.906 21.415 12.924 ;
     RECT  21.415 9.756 21.443 12.924 ;
     RECT  20.507 3.186 21.479 3.744 ;
     RECT  21.443 11.178 21.479 12.924 ;
     RECT  21.379 14.958 21.479 16.164 ;
     RECT  21.307 18.468 21.479 19.062 ;
     RECT  21.479 3.186 21.515 3.204 ;
     RECT  20.543 7.164 21.515 7.344 ;
     RECT  21.443 9.756 21.515 10.422 ;
     RECT  21.479 11.916 21.515 12.924 ;
     RECT  21.479 15.534 21.515 16.128 ;
     RECT  21.415 16.92 21.515 17.244 ;
     RECT  21.479 18.468 21.515 18.486 ;
     RECT  20.579 6.084 21.587 6.102 ;
     RECT  21.515 10.404 21.587 10.422 ;
    LAYER M3 ;
     RECT  4.968 1.957 4.986 2.029 ;
     RECT  6.084 1.957 6.102 2.029 ;
     RECT  7.596 1.723 7.614 2.029 ;
     RECT  4.716 2.029 4.986 2.101 ;
     RECT  7.2 2.029 7.614 2.101 ;
     RECT  10.8 2.101 10.818 2.143 ;
     RECT  4.716 2.101 5.274 2.191 ;
     RECT  6.084 2.029 6.138 2.191 ;
     RECT  6.984 2.101 8.226 2.191 ;
     RECT  9.108 2.029 9.126 2.191 ;
     RECT  2.415 2.143 2.505 2.251 ;
     RECT  3.744 2.191 3.762 2.251 ;
     RECT  0.144 2.227 0.162 2.263 ;
     RECT  2.415 2.251 3.762 2.299 ;
     RECT  4.716 2.191 9.126 2.299 ;
     RECT  2.415 2.299 9.126 2.371 ;
     RECT  15.915 2.143 16.005 2.371 ;
     RECT  13.215 2.143 13.305 2.413 ;
     RECT  15.624 2.371 16.005 2.413 ;
     RECT  18.615 2.143 18.705 2.413 ;
     RECT  0.108 2.263 0.162 2.443 ;
     RECT  15.624 2.413 16.197 2.489 ;
     RECT  2.34 2.371 9.126 2.605 ;
     RECT  10.515 2.143 10.818 2.641 ;
     RECT  15.915 2.489 16.197 2.641 ;
     RECT  17.208 2.263 17.226 2.641 ;
     RECT  0.108 2.443 0.846 2.827 ;
     RECT  18.615 2.413 18.897 3.001 ;
     RECT  2.304 2.605 9.126 3.067 ;
     RECT  15.915 2.641 17.226 3.073 ;
     RECT  18.072 3.001 18.897 3.073 ;
     RECT  15.915 3.073 18.897 3.145 ;
     RECT  2.304 3.067 9.162 3.307 ;
     RECT  1.728 3.307 9.162 3.355 ;
     RECT  1.728 3.355 9.27 3.379 ;
     RECT  15.915 3.145 18.954 3.451 ;
     RECT  15.915 3.451 19.026 3.541 ;
     RECT  15.915 3.541 19.098 3.641 ;
     RECT  1.728 3.379 9.522 3.721 ;
     RECT  15.048 2.731 15.066 3.721 ;
     RECT  21.492 3.181 21.51 3.721 ;
     RECT  21.456 3.721 21.51 3.821 ;
     RECT  1.728 3.721 9.594 3.919 ;
     RECT  10.515 2.641 11.214 3.919 ;
     RECT  20.484 3.811 20.502 3.979 ;
     RECT  21.456 3.821 21.474 4.109 ;
     RECT  0.108 2.827 0.918 4.205 ;
     RECT  0.324 4.205 0.918 4.253 ;
     RECT  0.324 4.253 0.846 4.487 ;
     RECT  15.915 3.641 19.026 4.495 ;
     RECT  15.915 4.495 19.134 4.649 ;
     RECT  12.024 3.541 12.042 4.657 ;
     RECT  15.048 3.721 15.138 4.693 ;
     RECT  12.024 4.657 12.078 4.699 ;
     RECT  13.215 2.413 13.497 4.891 ;
     RECT  14.724 4.693 15.138 4.891 ;
     RECT  15.915 4.649 18.897 4.891 ;
     RECT  19.908 3.979 20.502 4.919 ;
     RECT  14.724 4.891 18.897 4.963 ;
     RECT  1.728 3.919 11.214 5.029 ;
     RECT  11.952 4.699 12.366 5.029 ;
     RECT  14.256 4.963 18.897 5.029 ;
     RECT  1.728 5.029 12.366 5.063 ;
     RECT  14.22 5.029 18.897 5.069 ;
     RECT  2.196 5.063 12.366 5.071 ;
     RECT  13.104 4.891 13.497 5.071 ;
     RECT  14.256 5.069 18.897 5.189 ;
     RECT  19.908 4.919 20.466 5.189 ;
     RECT  2.196 5.071 13.497 5.297 ;
     RECT  0.324 4.487 0.342 5.323 ;
     RECT  0.144 5.323 0.342 5.501 ;
     RECT  0.216 5.501 0.342 5.539 ;
     RECT  0.216 5.539 0.486 5.575 ;
     RECT  0.216 5.575 0.558 5.597 ;
     RECT  2.268 5.297 13.497 5.645 ;
     RECT  11.952 5.645 13.497 5.729 ;
     RECT  19.908 5.189 19.926 5.729 ;
     RECT  15.048 5.189 18.897 5.971 ;
     RECT  15.048 5.971 18.954 6.079 ;
     RECT  15.048 6.079 18.99 6.115 ;
     RECT  0.468 5.597 0.558 6.125 ;
     RECT  0.468 6.125 0.486 6.221 ;
     RECT  20.196 6.151 20.214 6.241 ;
     RECT  2.268 5.645 11.214 6.305 ;
     RECT  20.196 6.241 20.574 6.691 ;
     RECT  2.304 6.305 11.214 7.051 ;
     RECT  15.048 6.115 19.314 7.087 ;
     RECT  21.564 6.079 21.582 7.147 ;
     RECT  2.268 7.051 11.214 7.321 ;
     RECT  11.952 5.729 11.97 7.321 ;
     RECT  21.492 7.147 21.582 7.373 ;
     RECT  14.832 7.087 19.314 7.435 ;
     RECT  20.052 6.691 20.574 7.435 ;
     RECT  2.268 7.321 11.97 7.501 ;
     RECT  0.108 6.619 0.126 7.531 ;
     RECT  0.108 7.531 0.342 7.661 ;
     RECT  2.268 7.501 12.114 7.691 ;
     RECT  0.108 7.661 0.234 7.925 ;
     RECT  0.18 7.925 0.234 7.949 ;
     RECT  14.832 7.435 20.574 8.203 ;
     RECT  0.324 8.395 0.342 8.525 ;
     RECT  13.215 5.729 13.497 8.581 ;
     RECT  14.652 8.203 20.574 8.581 ;
     RECT  21.564 7.373 21.582 8.587 ;
     RECT  13.215 8.581 20.574 8.699 ;
     RECT  14.256 8.699 20.574 8.717 ;
     RECT  21.42 8.587 21.582 8.765 ;
     RECT  19.908 8.717 20.574 9.101 ;
     RECT  2.268 7.691 12.042 9.121 ;
     RECT  2.268 9.121 12.186 9.239 ;
     RECT  0.54 9.085 0.558 9.259 ;
     RECT  0.54 9.259 0.666 9.485 ;
     RECT  19.908 9.101 20.538 9.485 ;
     RECT  2.268 9.239 12.042 9.739 ;
     RECT  21.564 8.765 21.582 9.739 ;
     RECT  21.492 9.739 21.582 9.751 ;
     RECT  21.42 9.751 21.582 9.835 ;
     RECT  2.232 9.739 12.042 9.887 ;
     RECT  19.908 9.485 20.502 9.923 ;
     RECT  14.256 8.717 19.134 9.965 ;
     RECT  13.215 8.699 13.497 10.165 ;
     RECT  14.256 9.965 19.062 10.165 ;
     RECT  20.196 9.923 20.502 10.219 ;
     RECT  20.196 10.219 20.538 10.349 ;
     RECT  21.348 9.835 21.582 10.427 ;
     RECT  0.252 9.895 0.27 10.459 ;
     RECT  0.144 10.459 0.27 10.507 ;
     RECT  2.268 9.887 12.042 10.597 ;
     RECT  0.144 10.507 0.342 10.637 ;
     RECT  21.348 10.427 21.51 10.699 ;
     RECT  13.215 10.165 19.062 10.705 ;
     RECT  0.18 10.637 0.27 10.814 ;
     RECT  13.215 10.705 19.134 10.831 ;
     RECT  0.18 10.814 0.198 10.925 ;
     RECT  2.268 10.597 12.078 11.083 ;
     RECT  1.98 11.083 12.078 11.129 ;
     RECT  13.104 10.831 19.134 11.129 ;
     RECT  20.412 10.349 20.538 11.309 ;
     RECT  13.104 11.129 13.497 11.408 ;
     RECT  14.256 11.129 19.134 11.515 ;
     RECT  1.98 11.129 12.042 11.543 ;
     RECT  21.276 10.699 21.51 11.611 ;
     RECT  14.256 11.515 19.494 11.659 ;
     RECT  0.324 11.563 0.342 11.693 ;
     RECT  14.256 11.659 19.926 11.885 ;
     RECT  2.304 11.543 12.042 11.939 ;
     RECT  21.24 11.611 21.51 11.981 ;
     RECT  21.312 11.981 21.51 12.173 ;
     RECT  19.944 12.055 20.538 12.365 ;
     RECT  0.324 12.427 0.342 12.487 ;
     RECT  14.256 11.885 19.206 12.587 ;
     RECT  0.108 12.487 0.342 12.631 ;
     RECT  1.26 12.619 1.278 12.631 ;
     RECT  11.736 11.939 12.042 12.749 ;
     RECT  0.108 12.631 1.278 12.845 ;
     RECT  19.944 12.365 20.43 12.845 ;
     RECT  11.952 12.749 11.97 12.857 ;
     RECT  21.42 12.173 21.51 12.929 ;
     RECT  20.412 12.845 20.43 12.941 ;
     RECT  2.304 11.939 10.962 12.991 ;
     RECT  2.304 12.991 11.142 13.003 ;
     RECT  0.108 12.845 1.17 13.085 ;
     RECT  0.108 13.085 0.558 13.133 ;
     RECT  0.54 13.133 0.558 13.229 ;
     RECT  14.256 12.587 19.098 13.469 ;
     RECT  20.484 13.099 20.502 13.469 ;
     RECT  21.42 12.929 21.438 13.483 ;
     RECT  2.268 13.003 11.142 13.603 ;
     RECT  13.215 11.408 13.497 13.639 ;
     RECT  2.268 13.603 11.214 13.837 ;
     RECT  2.268 13.837 11.358 13.963 ;
     RECT  2.232 13.963 11.358 13.981 ;
     RECT  14.4 13.469 19.098 13.981 ;
     RECT  14.4 13.981 19.422 14.093 ;
     RECT  2.232 13.981 11.43 14.099 ;
     RECT  12.564 13.639 13.497 14.099 ;
     RECT  2.232 14.099 11.286 14.207 ;
     RECT  21.312 13.483 21.438 14.251 ;
     RECT  2.232 14.207 11.214 14.279 ;
     RECT  13.215 14.099 13.497 14.347 ;
     RECT  20.52 13.945 20.538 14.381 ;
     RECT  21.276 14.251 21.438 14.443 ;
     RECT  13.215 14.347 13.59 14.477 ;
     RECT  2.268 14.279 11.214 14.513 ;
     RECT  19.944 14.485 19.962 14.573 ;
     RECT  0.324 14.059 0.342 14.635 ;
     RECT  0.108 14.635 0.342 14.669 ;
     RECT  0.108 14.669 0.126 14.765 ;
     RECT  21.24 14.443 21.438 14.923 ;
     RECT  13.215 14.477 13.497 15.163 ;
     RECT  2.304 14.513 11.214 15.179 ;
     RECT  19.908 15.115 19.926 15.287 ;
     RECT  21.24 14.923 21.474 15.341 ;
     RECT  21.312 15.341 21.474 15.403 ;
     RECT  2.34 15.179 11.214 15.485 ;
     RECT  14.4 14.093 19.134 15.493 ;
     RECT  13.104 15.163 13.497 15.728 ;
     RECT  2.376 15.485 11.214 15.755 ;
     RECT  21.312 15.403 21.51 16.133 ;
     RECT  21.312 16.133 21.474 16.169 ;
     RECT  14.4 15.493 19.242 16.439 ;
     RECT  21.312 16.169 21.438 16.493 ;
     RECT  14.4 16.439 19.17 16.529 ;
     RECT  14.616 16.529 19.134 16.601 ;
     RECT  14.616 16.601 19.098 16.799 ;
     RECT  20.484 16.555 20.502 16.843 ;
     RECT  21.348 16.493 21.438 16.915 ;
     RECT  20.448 16.843 20.502 16.943 ;
     RECT  21.348 16.915 21.51 17.069 ;
     RECT  2.415 15.755 11.214 17.227 ;
     RECT  21.42 17.069 21.51 17.261 ;
     RECT  13.215 15.728 13.497 17.311 ;
     RECT  2.304 17.227 11.214 17.323 ;
     RECT  2.268 17.323 11.214 17.411 ;
     RECT  0.108 17.077 0.126 17.453 ;
     RECT  20.484 16.943 20.502 17.519 ;
     RECT  21.42 17.261 21.438 17.549 ;
     RECT  13.104 17.311 13.497 17.617 ;
     RECT  0.324 17.515 0.342 17.645 ;
     RECT  2.268 17.411 10.854 17.645 ;
     RECT  2.304 17.645 10.854 17.681 ;
     RECT  14.76 16.799 19.098 17.707 ;
     RECT  20.52 17.689 20.538 17.761 ;
     RECT  20.52 17.761 20.574 17.837 ;
     RECT  2.304 17.681 10.797 17.915 ;
     RECT  4.032 17.915 10.797 17.987 ;
     RECT  2.415 17.915 2.934 18.059 ;
     RECT  4.032 17.987 5.814 18.149 ;
     RECT  6.84 17.987 10.797 18.149 ;
     RECT  12.564 17.617 13.497 18.149 ;
     RECT  4.392 18.149 5.397 18.185 ;
     RECT  6.84 18.149 9.522 18.185 ;
     RECT  13.215 18.149 13.497 18.193 ;
     RECT  6.84 18.185 6.894 18.221 ;
     RECT  9.036 18.185 9.522 18.221 ;
     RECT  9.18 18.221 9.522 18.269 ;
     RECT  20.556 17.837 20.574 18.379 ;
     RECT  7.815 18.185 8.262 18.419 ;
     RECT  9.18 18.269 9.198 18.419 ;
     RECT  2.415 18.059 2.898 18.455 ;
     RECT  20.556 18.379 21.258 18.463 ;
     RECT  20.556 18.463 21.51 18.491 ;
     RECT  21.24 18.491 21.51 18.509 ;
     RECT  14.76 17.707 19.386 18.599 ;
     RECT  21.24 18.509 21.474 18.797 ;
     RECT  13.215 18.193 13.806 18.845 ;
     RECT  6.84 18.221 6.858 19.037 ;
     RECT  14.76 18.599 18.954 19.037 ;
     RECT  21.312 18.797 21.474 19.067 ;
     RECT  21.312 19.067 21.438 19.085 ;
     RECT  14.76 19.037 18.897 19.103 ;
     RECT  2.415 18.455 2.697 19.187 ;
     RECT  5.115 18.185 5.397 19.187 ;
     RECT  7.815 18.419 8.097 19.187 ;
     RECT  10.515 18.149 10.797 19.187 ;
     RECT  13.215 18.845 13.497 19.187 ;
     RECT  15.696 19.103 18.897 19.187 ;
     RECT  14.76 19.103 14.886 19.229 ;
     RECT  15.696 19.187 18.705 19.229 ;
     RECT  14.76 19.229 14.814 19.277 ;
     RECT  20.484 18.571 20.502 19.277 ;
     RECT  14.76 19.277 14.778 19.301 ;
     RECT  15.696 19.229 16.005 19.301 ;
     RECT  21.42 19.085 21.438 19.325 ;
     RECT  15.768 19.301 16.005 19.337 ;
     RECT  16.92 19.229 18.705 19.337 ;
     RECT  17.352 19.337 18.705 19.373 ;
     RECT  17.352 19.373 17.37 19.379 ;
     RECT  2.415 19.187 2.505 19.457 ;
     RECT  5.115 19.187 5.205 19.457 ;
     RECT  7.815 19.187 7.905 19.457 ;
     RECT  10.515 19.187 10.605 19.457 ;
     RECT  13.215 19.187 13.305 19.457 ;
     RECT  15.915 19.337 16.005 19.457 ;
     RECT  18.615 19.373 18.705 19.457 ;
    LAYER M4 ;
     RECT  0.084 2.448 0.097 2.472 ;
     RECT  0.06 2.472 0.097 2.544 ;
     RECT  0.084 2.544 0.097 2.568 ;
     RECT  0.06 2.568 0.097 2.64 ;
     RECT  0.084 2.64 0.097 2.664 ;
     RECT  0.06 2.664 0.097 2.736 ;
     RECT  0.084 2.736 0.097 2.76 ;
     RECT  0.06 2.76 0.097 2.832 ;
     RECT  0.084 2.832 0.097 2.856 ;
     RECT  0.06 2.856 0.097 2.928 ;
     RECT  0.084 2.928 0.097 2.952 ;
     RECT  0.06 2.952 0.097 3.024 ;
     RECT  0.084 3.024 0.097 3.048 ;
     RECT  0.06 3.048 0.097 3.12 ;
     RECT  0.084 3.12 0.097 3.144 ;
     RECT  0.06 3.144 0.097 3.216 ;
     RECT  0.084 3.216 0.097 3.24 ;
     RECT  0.06 3.24 0.097 3.312 ;
     RECT  0.084 3.312 0.097 3.336 ;
     RECT  0.06 3.336 0.097 3.408 ;
     RECT  0.084 3.408 0.097 3.432 ;
     RECT  0.06 3.432 0.097 3.504 ;
     RECT  0.084 3.504 0.097 3.528 ;
     RECT  0.06 3.528 0.097 3.6 ;
     RECT  0.084 3.6 0.097 3.624 ;
     RECT  0.06 3.624 0.097 3.696 ;
     RECT  0.084 3.696 0.097 3.72 ;
     RECT  0.06 3.72 0.097 3.792 ;
     RECT  0.084 3.792 0.097 3.816 ;
     RECT  0.06 3.816 0.097 3.888 ;
     RECT  0.084 3.888 0.097 3.912 ;
     RECT  0.06 3.912 0.097 3.984 ;
     RECT  0.084 3.984 0.097 4.008 ;
     RECT  0.06 4.008 0.097 4.08 ;
     RECT  0.084 4.08 0.097 4.104 ;
     RECT  0.06 4.104 0.097 4.176 ;
     RECT  0.084 4.176 0.097 4.2 ;
     RECT  0.06 4.2 0.097 4.272 ;
     RECT  0.084 4.272 0.097 4.296 ;
     RECT  0.06 4.296 0.097 4.368 ;
     RECT  0.084 4.368 0.097 4.392 ;
     RECT  0.06 4.392 0.097 4.464 ;
     RECT  0.084 4.464 0.097 4.488 ;
     RECT  0.06 4.488 0.097 4.56 ;
     RECT  0.084 4.56 0.097 4.584 ;
     RECT  0.06 4.584 0.097 4.656 ;
     RECT  0.084 4.656 0.097 4.68 ;
     RECT  0.06 4.68 0.097 4.752 ;
     RECT  0.084 4.752 0.097 4.776 ;
     RECT  0.06 4.776 0.097 4.848 ;
     RECT  0.084 4.848 0.097 4.872 ;
     RECT  0.06 4.872 0.097 4.944 ;
     RECT  0.084 4.944 0.097 4.968 ;
     RECT  0.06 4.968 0.097 5.04 ;
     RECT  0.084 5.04 0.097 5.064 ;
     RECT  0.06 5.064 0.097 5.136 ;
     RECT  0.084 5.136 0.097 5.16 ;
     RECT  0.06 5.16 0.097 5.232 ;
     RECT  0.084 5.232 0.097 5.256 ;
     RECT  0.06 5.256 0.097 5.328 ;
     RECT  0.084 5.328 0.097 5.352 ;
     RECT  0.06 5.352 0.097 5.424 ;
     RECT  0.084 5.424 0.097 5.448 ;
     RECT  0.06 5.448 0.097 5.52 ;
     RECT  0.084 5.52 0.097 5.544 ;
     RECT  0.06 5.544 0.097 5.616 ;
     RECT  0.084 5.616 0.097 5.64 ;
     RECT  0.06 5.64 0.097 5.712 ;
     RECT  0.084 5.712 0.097 5.736 ;
     RECT  0.06 5.736 0.097 5.808 ;
     RECT  0.084 5.808 0.097 5.832 ;
     RECT  0.06 5.832 0.097 5.904 ;
     RECT  0.084 5.904 0.097 5.928 ;
     RECT  0.06 5.928 0.097 6 ;
     RECT  0.084 6 0.097 6.024 ;
     RECT  0.06 6.024 0.097 6.096 ;
     RECT  0.084 6.096 0.097 6.12 ;
     RECT  0.06 6.12 0.097 6.192 ;
     RECT  0.084 6.192 0.097 6.216 ;
     RECT  0.06 6.216 0.097 6.288 ;
     RECT  0.084 6.288 0.097 6.312 ;
     RECT  0.06 6.312 0.097 6.384 ;
     RECT  0.084 6.384 0.097 6.408 ;
     RECT  0.06 6.408 0.097 6.48 ;
     RECT  0.084 6.48 0.097 6.504 ;
     RECT  0.06 6.504 0.097 6.576 ;
     RECT  0.084 6.576 0.097 6.6 ;
     RECT  0.06 6.6 0.097 6.672 ;
     RECT  0.084 6.672 0.097 6.696 ;
     RECT  0.06 6.696 0.097 6.768 ;
     RECT  0.084 6.768 0.097 6.792 ;
     RECT  0.06 6.792 0.097 6.864 ;
     RECT  0.084 6.864 0.097 6.888 ;
     RECT  0.06 6.888 0.097 6.96 ;
     RECT  0.084 6.96 0.097 6.984 ;
     RECT  0.06 6.984 0.097 7.056 ;
     RECT  0.084 7.056 0.097 7.08 ;
     RECT  0.06 7.08 0.097 7.152 ;
     RECT  0.084 7.152 0.097 7.176 ;
     RECT  0.06 7.176 0.097 7.248 ;
     RECT  0.084 7.248 0.097 7.272 ;
     RECT  0.06 7.272 0.097 7.344 ;
     RECT  0.084 7.344 0.097 7.368 ;
     RECT  0.06 7.368 0.097 7.44 ;
     RECT  0.084 7.44 0.097 7.464 ;
     RECT  0.06 7.464 0.097 7.536 ;
     RECT  0.084 7.536 0.097 7.56 ;
     RECT  0.06 7.56 0.097 7.632 ;
     RECT  0.084 7.632 0.097 7.656 ;
     RECT  0.06 7.656 0.097 7.728 ;
     RECT  0.084 7.728 0.097 7.752 ;
     RECT  0.06 7.752 0.097 7.824 ;
     RECT  0.084 7.824 0.097 7.848 ;
     RECT  0.06 7.848 0.097 7.92 ;
     RECT  0.084 7.92 0.097 7.944 ;
     RECT  0.06 7.944 0.097 8.016 ;
     RECT  0.084 8.016 0.097 8.04 ;
     RECT  0.06 8.04 0.097 8.112 ;
     RECT  0.084 8.112 0.097 8.136 ;
     RECT  0.06 8.136 0.097 8.208 ;
     RECT  0.084 8.208 0.097 8.232 ;
     RECT  0.06 8.232 0.097 8.304 ;
     RECT  0.084 8.304 0.097 8.328 ;
     RECT  0.06 8.328 0.097 8.4 ;
     RECT  0.084 8.4 0.097 8.424 ;
     RECT  0.06 8.424 0.097 8.496 ;
     RECT  0.084 8.496 0.097 8.52 ;
     RECT  0.06 8.52 0.097 8.592 ;
     RECT  0.084 8.592 0.097 8.616 ;
     RECT  0.06 8.616 0.097 8.688 ;
     RECT  0.084 8.688 0.097 8.712 ;
     RECT  0.06 8.712 0.097 8.784 ;
     RECT  0.084 8.784 0.097 8.808 ;
     RECT  0.06 8.808 0.097 8.88 ;
     RECT  0.084 8.88 0.097 8.904 ;
     RECT  0.06 8.904 0.097 8.976 ;
     RECT  0.084 8.976 0.097 9 ;
     RECT  0.06 9 0.097 9.072 ;
     RECT  0.084 9.072 0.097 9.096 ;
     RECT  0.06 9.096 0.097 9.168 ;
     RECT  0.084 9.168 0.097 9.192 ;
     RECT  0.06 9.192 0.097 9.264 ;
     RECT  0.084 9.264 0.097 9.288 ;
     RECT  0.06 9.288 0.097 9.36 ;
     RECT  0.084 9.36 0.097 9.384 ;
     RECT  0.06 9.384 0.097 9.456 ;
     RECT  0.084 9.456 0.097 9.48 ;
     RECT  0.06 9.48 0.097 9.552 ;
     RECT  0.084 9.552 0.097 9.576 ;
     RECT  0.06 9.576 0.097 9.648 ;
     RECT  0.084 9.648 0.097 9.672 ;
     RECT  0.06 9.672 0.097 9.744 ;
     RECT  0.084 9.744 0.097 9.768 ;
     RECT  0.06 9.768 0.097 9.84 ;
     RECT  0.084 9.84 0.097 9.864 ;
     RECT  0.06 9.864 0.097 9.936 ;
     RECT  0.084 9.936 0.097 9.96 ;
     RECT  0.06 9.96 0.097 10.032 ;
     RECT  0.084 10.032 0.097 10.056 ;
     RECT  0.06 10.056 0.097 10.128 ;
     RECT  0.084 10.128 0.097 10.152 ;
     RECT  0.06 10.152 0.097 10.224 ;
     RECT  0.084 10.224 0.097 10.248 ;
     RECT  0.06 10.248 0.097 10.32 ;
     RECT  0.084 10.32 0.097 10.344 ;
     RECT  0.06 10.344 0.097 10.416 ;
     RECT  0.084 10.416 0.097 10.44 ;
     RECT  0.06 10.44 0.097 10.512 ;
     RECT  0.084 10.512 0.097 10.536 ;
     RECT  0.06 10.536 0.097 10.608 ;
     RECT  0.084 10.608 0.097 10.632 ;
     RECT  0.06 10.632 0.097 10.704 ;
     RECT  0.084 10.704 0.097 10.728 ;
     RECT  0.06 10.728 0.097 10.8 ;
     RECT  0.084 10.8 0.097 10.824 ;
     RECT  0.06 10.824 0.097 10.896 ;
     RECT  0.084 10.896 0.097 10.92 ;
     RECT  0.06 10.92 0.097 10.992 ;
     RECT  0.084 10.992 0.097 11.016 ;
     RECT  0.06 11.016 0.097 11.088 ;
     RECT  0.084 11.088 0.097 11.112 ;
     RECT  0.06 11.112 0.097 11.184 ;
     RECT  0.084 11.184 0.097 11.208 ;
     RECT  0.06 11.208 0.097 11.28 ;
     RECT  0.084 11.28 0.097 11.304 ;
     RECT  0.06 11.304 0.097 11.376 ;
     RECT  0.084 11.376 0.097 11.4 ;
     RECT  0.06 11.4 0.097 11.472 ;
     RECT  0.084 11.472 0.097 11.496 ;
     RECT  0.06 11.496 0.097 11.568 ;
     RECT  0.084 11.568 0.097 11.592 ;
     RECT  0.06 11.592 0.097 11.664 ;
     RECT  0.084 11.664 0.097 11.688 ;
     RECT  0.06 11.688 0.097 11.76 ;
     RECT  0.084 11.76 0.097 11.784 ;
     RECT  0.06 11.784 0.097 11.856 ;
     RECT  0.084 11.856 0.097 11.88 ;
     RECT  0.06 11.88 0.097 11.952 ;
     RECT  0.084 11.952 0.097 11.976 ;
     RECT  0.06 11.976 0.097 12.048 ;
     RECT  0.084 12.048 0.097 12.072 ;
     RECT  0.06 12.072 0.097 12.144 ;
     RECT  0.084 12.144 0.097 12.168 ;
     RECT  0.06 12.168 0.097 12.24 ;
     RECT  0.084 12.24 0.097 12.264 ;
     RECT  0.06 12.264 0.097 12.336 ;
     RECT  0.084 12.336 0.097 12.36 ;
     RECT  0.06 12.36 0.097 12.432 ;
     RECT  0.084 12.432 0.097 12.456 ;
     RECT  0.06 12.456 0.097 12.528 ;
     RECT  0.084 12.528 0.097 12.552 ;
     RECT  0.06 12.552 0.097 12.624 ;
     RECT  0.084 12.624 0.097 12.648 ;
     RECT  0.06 12.648 0.097 12.72 ;
     RECT  0.084 12.72 0.097 12.744 ;
     RECT  0.06 12.744 0.097 12.816 ;
     RECT  0.084 12.816 0.097 12.84 ;
     RECT  0.06 12.84 0.097 12.912 ;
     RECT  0.084 12.912 0.097 12.936 ;
     RECT  0.06 12.936 0.097 13.008 ;
     RECT  0.084 13.008 0.097 13.032 ;
     RECT  0.06 13.032 0.097 13.104 ;
     RECT  0.084 13.104 0.097 13.128 ;
     RECT  0.06 13.128 0.097 13.2 ;
     RECT  0.084 13.2 0.097 13.224 ;
     RECT  0.06 13.224 0.097 13.296 ;
     RECT  0.084 13.296 0.097 13.32 ;
     RECT  0.06 13.32 0.097 13.392 ;
     RECT  0.084 13.392 0.097 13.416 ;
     RECT  0.06 13.416 0.097 13.488 ;
     RECT  0.084 13.488 0.097 13.512 ;
     RECT  0.06 13.512 0.097 13.584 ;
     RECT  0.084 13.584 0.097 13.608 ;
     RECT  0.06 13.608 0.097 13.68 ;
     RECT  0.084 13.68 0.097 13.704 ;
     RECT  0.06 13.704 0.097 13.776 ;
     RECT  0.084 13.776 0.097 13.8 ;
     RECT  0.06 13.8 0.097 13.872 ;
     RECT  0.084 13.872 0.097 13.896 ;
     RECT  0.06 13.896 0.097 13.968 ;
     RECT  0.084 13.968 0.097 13.992 ;
     RECT  0.06 13.992 0.097 14.064 ;
     RECT  0.084 14.064 0.097 14.088 ;
     RECT  0.06 14.088 0.097 14.16 ;
     RECT  0.084 14.16 0.097 14.184 ;
     RECT  0.06 14.184 0.097 14.256 ;
     RECT  0.084 14.256 0.097 14.28 ;
     RECT  0.06 14.28 0.097 14.352 ;
     RECT  0.084 14.352 0.097 14.376 ;
     RECT  0.06 14.376 0.097 14.448 ;
     RECT  0.084 14.448 0.097 14.472 ;
     RECT  0.06 14.472 0.097 14.544 ;
     RECT  0.084 14.544 0.097 14.568 ;
     RECT  0.06 14.568 0.097 14.64 ;
     RECT  0.084 14.64 0.097 14.664 ;
     RECT  0.097 2.448 0.857 14.76 ;
     RECT  0.857 2.736 2.408 14.76 ;
     RECT  0.084 17.04 2.408 17.064 ;
     RECT  0.06 17.064 2.408 17.136 ;
     RECT  0.084 17.136 2.408 17.16 ;
     RECT  0.06 17.16 2.408 17.232 ;
     RECT  0.084 17.232 2.408 17.256 ;
     RECT  0.06 17.256 2.408 17.328 ;
     RECT  0.084 17.328 2.408 17.352 ;
     RECT  0.06 17.352 2.408 17.424 ;
     RECT  0.084 17.424 2.408 17.448 ;
     RECT  0.06 17.448 2.408 17.52 ;
     RECT  0.084 17.52 2.408 17.544 ;
     RECT  0.06 17.544 2.408 17.616 ;
     RECT  0.084 17.616 2.408 17.64 ;
     RECT  0.06 17.64 2.408 17.712 ;
     RECT  0.084 17.712 2.408 17.736 ;
     RECT  2.408 2.148 2.512 19.452 ;
     RECT  2.512 2.256 2.704 19.182 ;
     RECT  2.704 17.136 2.765 17.736 ;
     RECT  2.704 2.256 2.873 14.76 ;
     RECT  2.765 17.616 2.909 17.736 ;
     RECT  2.909 17.616 3.089 17.64 ;
     RECT  2.873 2.256 3.949 3.816 ;
     RECT  2.873 4.848 3.949 14.664 ;
     RECT  2.704 15.936 3.949 16.152 ;
     RECT  3.949 2.256 4.597 16.152 ;
     RECT  4.201 17.232 4.597 17.256 ;
     RECT  4.597 2.256 4.789 17.256 ;
     RECT  4.789 2.256 5.108 17.4 ;
     RECT  5.108 2.148 5.212 19.452 ;
     RECT  5.212 2.256 5.404 19.182 ;
     RECT  5.404 2.256 6.361 17.16 ;
     RECT  6.361 2.208 6.433 17.16 ;
     RECT  6.433 2.208 7.189 17.976 ;
     RECT  6.829 19.008 7.189 19.032 ;
     RECT  7.189 2.208 7.525 19.032 ;
     RECT  7.525 1.728 7.625 19.032 ;
     RECT  7.625 2.148 7.808 19.032 ;
     RECT  7.808 2.148 7.912 19.452 ;
     RECT  7.912 2.418 8.104 19.182 ;
     RECT  8.104 2.832 8.633 13.08 ;
     RECT  8.633 2.832 8.669 8.04 ;
     RECT  8.104 14.112 9.137 19.032 ;
     RECT  8.669 3.024 9.497 8.04 ;
     RECT  9.497 3.024 10.508 3.048 ;
     RECT  9.497 4.128 10.508 8.04 ;
     RECT  8.633 9.264 10.508 13.08 ;
     RECT  9.137 14.208 10.508 19.032 ;
     RECT  10.508 2.148 10.612 19.452 ;
     RECT  10.612 2.418 10.804 19.182 ;
     RECT  10.804 3.024 10.901 3.048 ;
     RECT  10.804 4.128 10.901 5.064 ;
     RECT  10.901 4.752 11.905 5.064 ;
     RECT  11.905 4.752 11.941 5.64 ;
     RECT  11.941 4.704 13.208 5.64 ;
     RECT  10.804 7.632 13.208 9.288 ;
     RECT  10.804 10.848 13.208 19.032 ;
     RECT  13.208 2.148 13.312 19.452 ;
     RECT  13.312 2.418 13.504 19.182 ;
     RECT  13.504 10.848 14.785 19.032 ;
     RECT  14.785 10.848 14.861 19.272 ;
     RECT  13.504 4.752 15.908 5.064 ;
     RECT  13.504 7.632 15.908 9.288 ;
     RECT  14.861 10.944 15.908 19.272 ;
     RECT  15.908 2.148 16.012 19.452 ;
     RECT  16.012 2.418 16.204 19.272 ;
     RECT  16.204 7.632 17.341 19.272 ;
     RECT  16.204 4.656 17.561 5.064 ;
     RECT  17.561 4.704 18.608 5.064 ;
     RECT  18.421 6.624 18.608 6.648 ;
     RECT  17.341 7.632 18.608 19.368 ;
     RECT  18.608 2.148 18.712 19.452 ;
     RECT  18.712 2.418 18.904 19.32 ;
     RECT  18.904 6.864 19.897 8.808 ;
     RECT  18.904 9.792 19.897 19.32 ;
     RECT  19.897 3.984 20.437 4.392 ;
     RECT  20.437 3.984 20.473 4.584 ;
     RECT  19.897 6.864 21.449 19.32 ;
     RECT  20.473 3.888 21.481 4.584 ;
     RECT  21.481 3.792 21.516 3.816 ;
     RECT  21.481 3.816 21.564 3.888 ;
     RECT  21.481 3.888 21.516 3.912 ;
     RECT  21.481 3.912 21.564 3.984 ;
     RECT  21.481 3.984 21.516 4.008 ;
     RECT  21.481 4.008 21.564 4.08 ;
     RECT  21.481 4.08 21.516 4.104 ;
     RECT  21.481 4.104 21.564 4.176 ;
     RECT  21.481 4.176 21.516 4.2 ;
     RECT  21.481 4.2 21.564 4.272 ;
     RECT  21.481 4.272 21.516 4.296 ;
     RECT  21.481 4.296 21.564 4.368 ;
     RECT  21.481 4.368 21.516 4.392 ;
     RECT  21.481 4.392 21.564 4.464 ;
     RECT  21.481 4.464 21.516 4.488 ;
     RECT  21.481 4.488 21.564 4.56 ;
     RECT  21.481 4.56 21.516 4.584 ;
     RECT  21.449 6.864 21.516 6.888 ;
     RECT  21.449 6.888 21.564 6.96 ;
     RECT  21.449 6.96 21.516 6.984 ;
     RECT  21.449 6.984 21.564 7.056 ;
     RECT  21.449 7.056 21.516 7.08 ;
     RECT  21.449 7.08 21.564 7.152 ;
     RECT  21.449 7.152 21.516 7.176 ;
     RECT  21.449 7.176 21.564 7.248 ;
     RECT  21.449 7.248 21.516 7.272 ;
     RECT  21.449 7.272 21.564 7.344 ;
     RECT  21.449 7.344 21.516 7.368 ;
     RECT  21.449 7.368 21.564 7.44 ;
     RECT  21.449 7.44 21.516 7.464 ;
     RECT  21.449 7.464 21.564 7.536 ;
     RECT  21.449 7.536 21.516 7.56 ;
     RECT  21.449 7.56 21.564 7.632 ;
     RECT  21.449 7.632 21.516 7.656 ;
     RECT  21.449 7.656 21.564 7.728 ;
     RECT  21.449 7.728 21.516 7.752 ;
     RECT  21.449 7.752 21.564 7.824 ;
     RECT  21.449 7.824 21.516 7.848 ;
     RECT  21.449 7.848 21.564 7.92 ;
     RECT  21.449 7.92 21.516 7.944 ;
     RECT  21.449 7.944 21.564 8.016 ;
     RECT  21.449 8.016 21.516 8.04 ;
     RECT  21.449 8.04 21.564 8.112 ;
     RECT  21.449 8.112 21.516 8.136 ;
     RECT  21.449 8.136 21.564 8.208 ;
     RECT  21.449 8.208 21.516 8.232 ;
     RECT  21.449 8.232 21.564 8.304 ;
     RECT  21.449 8.304 21.516 8.328 ;
     RECT  21.449 8.328 21.564 8.4 ;
     RECT  21.449 8.4 21.516 8.424 ;
     RECT  21.449 8.424 21.564 8.496 ;
     RECT  21.449 8.496 21.516 8.52 ;
     RECT  21.449 8.52 21.564 8.592 ;
     RECT  21.449 8.592 21.516 8.616 ;
     RECT  21.449 8.616 21.564 8.688 ;
     RECT  21.449 8.688 21.516 8.712 ;
     RECT  21.449 8.712 21.564 8.784 ;
     RECT  21.449 8.784 21.516 8.808 ;
     RECT  21.449 8.808 21.564 8.88 ;
     RECT  21.449 8.88 21.516 8.904 ;
     RECT  21.449 8.904 21.564 8.976 ;
     RECT  21.449 8.976 21.516 9 ;
     RECT  21.449 9 21.564 9.072 ;
     RECT  21.449 9.072 21.516 9.096 ;
     RECT  21.449 9.096 21.564 9.168 ;
     RECT  21.449 9.168 21.516 9.192 ;
     RECT  21.449 9.192 21.564 9.264 ;
     RECT  21.449 9.264 21.516 9.288 ;
     RECT  21.449 9.288 21.564 9.36 ;
     RECT  21.449 9.36 21.516 9.384 ;
     RECT  21.449 9.384 21.564 9.456 ;
     RECT  21.449 9.456 21.516 9.48 ;
     RECT  21.449 9.48 21.564 9.552 ;
     RECT  21.449 9.552 21.516 9.576 ;
     RECT  21.449 9.576 21.564 9.648 ;
     RECT  21.449 9.648 21.516 9.672 ;
     RECT  21.449 9.672 21.564 9.744 ;
     RECT  21.449 9.744 21.516 9.768 ;
     RECT  21.449 9.768 21.564 9.84 ;
     RECT  21.449 9.84 21.516 9.864 ;
     RECT  21.449 9.864 21.564 9.936 ;
     RECT  21.449 9.936 21.516 9.96 ;
     RECT  21.449 9.96 21.564 10.032 ;
     RECT  21.449 10.032 21.516 10.056 ;
     RECT  21.449 10.056 21.564 10.128 ;
     RECT  21.449 10.128 21.516 10.152 ;
     RECT  21.449 10.152 21.564 10.224 ;
     RECT  21.449 10.224 21.516 10.248 ;
     RECT  21.449 10.248 21.564 10.32 ;
     RECT  21.449 10.32 21.516 10.344 ;
     RECT  21.449 10.344 21.564 10.416 ;
     RECT  21.449 10.416 21.516 10.44 ;
     RECT  21.449 10.44 21.564 10.512 ;
     RECT  21.449 10.512 21.516 10.536 ;
     RECT  21.449 10.536 21.564 10.608 ;
     RECT  21.449 10.608 21.516 10.632 ;
     RECT  21.449 10.632 21.564 10.704 ;
     RECT  21.449 10.704 21.516 10.728 ;
     RECT  21.449 10.728 21.564 10.8 ;
     RECT  21.449 10.8 21.516 10.824 ;
     RECT  21.449 10.824 21.564 10.896 ;
     RECT  21.449 10.896 21.516 10.92 ;
     RECT  21.449 10.92 21.564 10.992 ;
     RECT  21.449 10.992 21.516 11.016 ;
     RECT  21.449 11.016 21.564 11.088 ;
     RECT  21.449 11.088 21.516 11.112 ;
     RECT  21.449 11.112 21.564 11.184 ;
     RECT  21.449 11.184 21.516 11.208 ;
     RECT  21.449 11.208 21.564 11.28 ;
     RECT  21.449 11.28 21.516 11.304 ;
     RECT  21.449 11.304 21.564 11.376 ;
     RECT  21.449 11.376 21.516 11.4 ;
     RECT  21.449 11.4 21.564 11.472 ;
     RECT  21.449 11.472 21.516 11.496 ;
     RECT  21.449 11.496 21.564 11.568 ;
     RECT  21.449 11.568 21.516 11.592 ;
     RECT  21.449 11.592 21.564 11.664 ;
     RECT  21.449 11.664 21.516 11.688 ;
     RECT  21.449 11.688 21.564 11.76 ;
     RECT  21.449 11.76 21.516 11.784 ;
     RECT  21.449 11.784 21.564 11.856 ;
     RECT  21.449 11.856 21.516 11.88 ;
     RECT  21.449 11.88 21.564 11.952 ;
     RECT  21.449 11.952 21.516 11.976 ;
     RECT  21.449 11.976 21.564 12.048 ;
     RECT  21.449 12.048 21.516 12.072 ;
     RECT  21.449 12.072 21.564 12.144 ;
     RECT  21.449 12.144 21.516 12.168 ;
     RECT  21.449 12.168 21.564 12.24 ;
     RECT  21.449 12.24 21.516 12.264 ;
     RECT  21.449 12.264 21.564 12.336 ;
     RECT  21.449 12.336 21.516 12.36 ;
     RECT  21.449 12.36 21.564 12.432 ;
     RECT  21.449 12.432 21.516 12.456 ;
     RECT  21.449 12.456 21.564 12.528 ;
     RECT  21.449 12.528 21.516 12.552 ;
     RECT  21.449 12.552 21.564 12.624 ;
     RECT  21.449 12.624 21.516 12.648 ;
     RECT  21.449 12.648 21.564 12.72 ;
     RECT  21.449 12.72 21.516 12.744 ;
     RECT  21.449 12.744 21.564 12.816 ;
     RECT  21.449 12.816 21.516 12.84 ;
     RECT  21.449 12.84 21.564 12.912 ;
     RECT  21.449 12.912 21.516 12.936 ;
     RECT  21.449 12.936 21.564 13.008 ;
     RECT  21.449 13.008 21.516 13.032 ;
     RECT  21.449 13.032 21.564 13.104 ;
     RECT  21.449 13.104 21.516 13.128 ;
     RECT  21.449 13.128 21.564 13.2 ;
     RECT  21.449 13.2 21.516 13.224 ;
     RECT  21.449 13.224 21.564 13.296 ;
     RECT  21.449 13.296 21.516 13.32 ;
     RECT  21.449 13.32 21.564 13.392 ;
     RECT  21.449 13.392 21.516 13.416 ;
     RECT  21.449 13.416 21.564 13.488 ;
     RECT  21.449 13.488 21.516 13.512 ;
     RECT  21.449 13.512 21.564 13.584 ;
     RECT  21.449 13.584 21.516 13.608 ;
     RECT  21.449 13.608 21.564 13.68 ;
     RECT  21.449 13.68 21.516 13.704 ;
     RECT  21.449 13.704 21.564 13.776 ;
     RECT  21.449 13.776 21.516 13.8 ;
     RECT  21.449 13.8 21.564 13.872 ;
     RECT  21.449 13.872 21.516 13.896 ;
     RECT  21.449 13.896 21.564 13.968 ;
     RECT  21.449 13.968 21.516 13.992 ;
     RECT  21.449 13.992 21.564 14.064 ;
     RECT  21.449 14.064 21.516 14.088 ;
     RECT  21.449 14.088 21.564 14.16 ;
     RECT  21.449 14.16 21.516 14.184 ;
     RECT  21.449 14.184 21.564 14.256 ;
     RECT  21.449 14.256 21.516 14.28 ;
     RECT  21.449 14.28 21.564 14.352 ;
     RECT  21.449 14.352 21.516 14.376 ;
     RECT  21.449 14.376 21.564 14.448 ;
     RECT  21.449 14.448 21.516 14.472 ;
     RECT  21.449 14.472 21.564 14.544 ;
     RECT  21.449 14.544 21.516 14.568 ;
     RECT  21.449 14.568 21.564 14.64 ;
     RECT  21.449 14.64 21.516 14.664 ;
     RECT  21.449 14.664 21.564 14.736 ;
     RECT  21.449 14.736 21.516 14.76 ;
     RECT  21.449 14.76 21.564 14.832 ;
     RECT  21.449 14.832 21.516 14.856 ;
     RECT  21.449 14.856 21.564 14.928 ;
     RECT  21.449 14.928 21.516 14.952 ;
     RECT  21.449 14.952 21.564 15.024 ;
     RECT  21.449 15.024 21.516 15.048 ;
     RECT  21.449 15.048 21.564 15.12 ;
     RECT  21.449 15.12 21.516 15.144 ;
     RECT  21.449 15.144 21.564 15.216 ;
     RECT  21.449 15.216 21.516 15.24 ;
     RECT  21.449 15.24 21.564 15.312 ;
     RECT  21.449 15.312 21.516 15.336 ;
     RECT  21.449 15.336 21.564 15.408 ;
     RECT  21.449 15.408 21.516 15.432 ;
     RECT  21.449 15.432 21.564 15.504 ;
     RECT  21.449 15.504 21.516 15.528 ;
     RECT  21.449 15.528 21.564 15.6 ;
     RECT  21.449 15.6 21.516 15.624 ;
     RECT  21.449 15.624 21.564 15.696 ;
     RECT  21.449 15.696 21.516 15.72 ;
     RECT  21.449 15.72 21.564 15.792 ;
     RECT  21.449 15.792 21.516 15.816 ;
     RECT  21.449 15.816 21.564 15.888 ;
     RECT  21.449 15.888 21.516 15.912 ;
     RECT  21.449 15.912 21.564 15.984 ;
     RECT  21.449 15.984 21.516 16.008 ;
     RECT  21.449 16.008 21.564 16.08 ;
     RECT  21.449 16.08 21.516 16.104 ;
     RECT  21.449 16.104 21.564 16.176 ;
     RECT  21.449 16.176 21.516 16.2 ;
     RECT  21.449 16.2 21.564 16.272 ;
     RECT  21.449 16.272 21.516 16.296 ;
     RECT  21.449 16.296 21.564 16.368 ;
     RECT  21.449 16.368 21.516 16.392 ;
     RECT  21.449 16.392 21.564 16.464 ;
     RECT  21.449 16.464 21.516 16.488 ;
     RECT  21.449 16.488 21.564 16.56 ;
     RECT  21.449 16.56 21.516 16.584 ;
     RECT  21.449 16.584 21.564 16.656 ;
     RECT  21.449 16.656 21.516 16.68 ;
     RECT  21.449 16.68 21.564 16.752 ;
     RECT  21.449 16.752 21.516 16.776 ;
     RECT  21.449 16.776 21.564 16.848 ;
     RECT  21.449 16.848 21.516 16.872 ;
     RECT  21.449 16.872 21.564 16.944 ;
     RECT  21.449 16.944 21.516 16.968 ;
     RECT  21.449 16.968 21.564 17.04 ;
     RECT  21.449 17.04 21.516 17.064 ;
     RECT  21.449 17.064 21.564 17.136 ;
     RECT  21.449 17.136 21.516 17.16 ;
     RECT  21.449 17.16 21.564 17.232 ;
     RECT  21.449 17.232 21.516 17.256 ;
     RECT  21.449 17.256 21.564 17.328 ;
     RECT  21.449 17.328 21.516 17.352 ;
     RECT  21.449 17.352 21.564 17.424 ;
     RECT  21.449 17.424 21.516 17.448 ;
     RECT  21.449 17.448 21.564 17.52 ;
     RECT  21.449 17.52 21.516 17.544 ;
     RECT  21.449 17.544 21.564 17.616 ;
     RECT  21.449 17.616 21.516 17.64 ;
     RECT  21.449 17.64 21.564 17.712 ;
     RECT  21.449 17.712 21.516 17.736 ;
     RECT  21.449 17.736 21.564 17.808 ;
     RECT  21.449 17.808 21.516 17.832 ;
     RECT  21.449 17.832 21.564 17.904 ;
     RECT  21.449 17.904 21.516 17.928 ;
     RECT  21.449 17.928 21.564 18 ;
     RECT  21.449 18 21.516 18.024 ;
     RECT  21.449 18.024 21.564 18.096 ;
     RECT  21.449 18.096 21.516 18.12 ;
     RECT  21.449 18.12 21.564 18.192 ;
     RECT  21.449 18.192 21.516 18.216 ;
     RECT  21.449 18.216 21.564 18.288 ;
     RECT  21.449 18.288 21.516 18.312 ;
     RECT  21.449 18.312 21.564 18.384 ;
     RECT  21.449 18.384 21.516 18.408 ;
     RECT  21.449 18.408 21.564 18.48 ;
     RECT  21.449 18.48 21.516 18.504 ;
     RECT  21.449 18.504 21.564 18.576 ;
     RECT  21.449 18.576 21.516 18.6 ;
     RECT  21.449 18.6 21.564 18.672 ;
     RECT  21.449 18.672 21.516 18.696 ;
     RECT  21.449 18.696 21.564 18.768 ;
     RECT  21.449 18.768 21.516 18.792 ;
     RECT  21.449 18.792 21.564 18.864 ;
     RECT  21.449 18.864 21.516 18.888 ;
     RECT  21.449 18.888 21.564 18.96 ;
     RECT  21.449 18.96 21.516 18.984 ;
     RECT  21.449 18.984 21.564 19.056 ;
     RECT  21.449 19.056 21.516 19.08 ;
    LAYER M5 ;
     RECT  7.464 0.016 7.536 0.084 ;
     RECT  7.44 0.084 7.56 2.137 ;
     RECT  2.4 2.137 2.52 2.151 ;
     RECT  5.1 2.137 5.22 2.151 ;
     RECT  7.44 2.137 7.92 2.151 ;
     RECT  10.5 2.137 10.62 2.151 ;
     RECT  13.2 2.137 13.32 2.151 ;
     RECT  15.9 2.137 16.02 2.151 ;
     RECT  18.6 2.137 18.72 2.151 ;
     RECT  7.44 2.151 8.112 2.197 ;
     RECT  2.4 2.151 2.712 2.389 ;
     RECT  5.1 2.151 5.412 2.389 ;
     RECT  4.992 2.389 5.412 2.533 ;
     RECT  6.672 2.197 8.112 2.533 ;
     RECT  4.992 2.533 8.112 2.773 ;
     RECT  2.4 2.389 3.432 2.915 ;
     RECT  0.192 2.965 0.216 3.155 ;
     RECT  4.8 2.773 8.112 3.157 ;
     RECT  4.8 3.157 8.232 3.349 ;
     RECT  4.512 3.349 8.232 3.397 ;
     RECT  4.512 3.397 8.472 3.829 ;
     RECT  4.176 3.829 8.472 4.501 ;
     RECT  4.176 4.501 8.568 4.741 ;
     RECT  0.144 4.693 0.168 4.979 ;
     RECT  4.176 4.741 9.048 4.979 ;
     RECT  4.176 4.979 8.568 5.605 ;
     RECT  3.888 5.605 8.568 6.323 ;
     RECT  2.4 2.915 2.712 6.613 ;
     RECT  18.6 2.151 18.912 6.613 ;
     RECT  3.888 6.323 8.52 7.139 ;
     RECT  0.288 6.469 0.312 7.621 ;
     RECT  3.936 7.139 8.52 7.667 ;
     RECT  0.144 7.621 0.312 7.955 ;
     RECT  3.936 7.667 8.472 8.051 ;
     RECT  0.144 7.955 0.168 8.531 ;
     RECT  2.4 6.613 2.856 8.965 ;
     RECT  3.936 8.051 8.28 8.965 ;
     RECT  18.432 6.613 18.912 9.491 ;
     RECT  2.4 8.965 8.28 10.117 ;
     RECT  2.4 10.117 8.376 10.405 ;
     RECT  2.4 10.405 8.808 10.789 ;
     RECT  2.4 10.789 9.528 10.883 ;
     RECT  21.408 11.413 21.432 11.987 ;
     RECT  4.128 10.883 9.528 12.035 ;
     RECT  2.4 10.883 2.856 12.275 ;
     RECT  4.704 12.035 9.528 12.467 ;
     RECT  4.704 12.467 8.808 12.563 ;
     RECT  0.144 11.509 0.168 12.803 ;
     RECT  14.832 12.517 14.856 12.803 ;
     RECT  21.408 13.333 21.432 13.619 ;
     RECT  0.144 13.909 0.168 14.195 ;
     RECT  21.408 14.629 21.432 14.819 ;
     RECT  4.704 12.563 8.376 15.155 ;
     RECT  6.912 15.155 8.376 15.443 ;
     RECT  6.912 15.443 8.112 16.019 ;
     RECT  21.408 16.021 21.432 16.403 ;
     RECT  7.008 16.019 8.112 16.595 ;
     RECT  4.704 15.155 5.88 17.123 ;
     RECT  4.8 17.123 5.88 17.171 ;
     RECT  4.8 17.171 5.412 17.411 ;
     RECT  0.144 17.461 0.168 17.651 ;
     RECT  2.4 12.275 2.712 19.449 ;
     RECT  5.1 17.411 5.412 19.449 ;
     RECT  7.8 16.595 8.112 19.449 ;
     RECT  10.5 2.151 10.812 19.449 ;
     RECT  13.2 2.151 13.512 19.449 ;
     RECT  15.9 2.151 16.212 19.449 ;
     RECT  18.6 9.491 18.912 19.449 ;
     RECT  2.4 19.449 2.52 19.463 ;
     RECT  5.1 19.449 5.22 19.463 ;
     RECT  7.8 19.449 7.92 19.463 ;
     RECT  10.5 19.449 10.62 19.463 ;
     RECT  13.2 19.449 13.32 19.463 ;
     RECT  15.9 19.449 16.02 19.463 ;
     RECT  18.6 19.449 18.72 19.463 ;
     RECT  5.412 2.197 6.672 2.533 ;
     RECT  3.432 2.773 4.8 2.915 ;
     RECT  2.712 2.915 4.8 3.349 ;
     RECT  2.712 3.349 4.512 3.829 ;
     RECT  2.712 3.829 4.176 5.605 ;
     RECT  9.048 4.741 10.5 4.979 ;
     RECT  2.712 5.605 3.888 6.613 ;
     RECT  2.856 6.613 3.888 7.139 ;
     RECT  2.856 7.139 3.936 8.965 ;
     RECT  9.528 10.789 10.5 12.467 ;
     RECT  2.856 10.883 4.128 12.035 ;
     RECT  21.408 11.987 21.42 13.333 ;
     RECT  13.512 12.517 14.832 12.803 ;
     RECT  14.856 12.517 15.9 12.803 ;
     RECT  21.408 13.619 21.42 14.629 ;
     RECT  21.408 14.819 21.42 16.021 ;
     RECT  5.88 15.155 6.912 16.019 ;
     RECT  5.88 16.019 7.008 16.595 ;
  END
END hbfd_rly_136_WE_rr
END LIBRARY
